VERSION 5.8 ;
BUSBITCHARS "[]" ;
DIVIDERCHAR "/" ;
UNITS
    DATABASE MICRONS 1000 ;
END UNITS

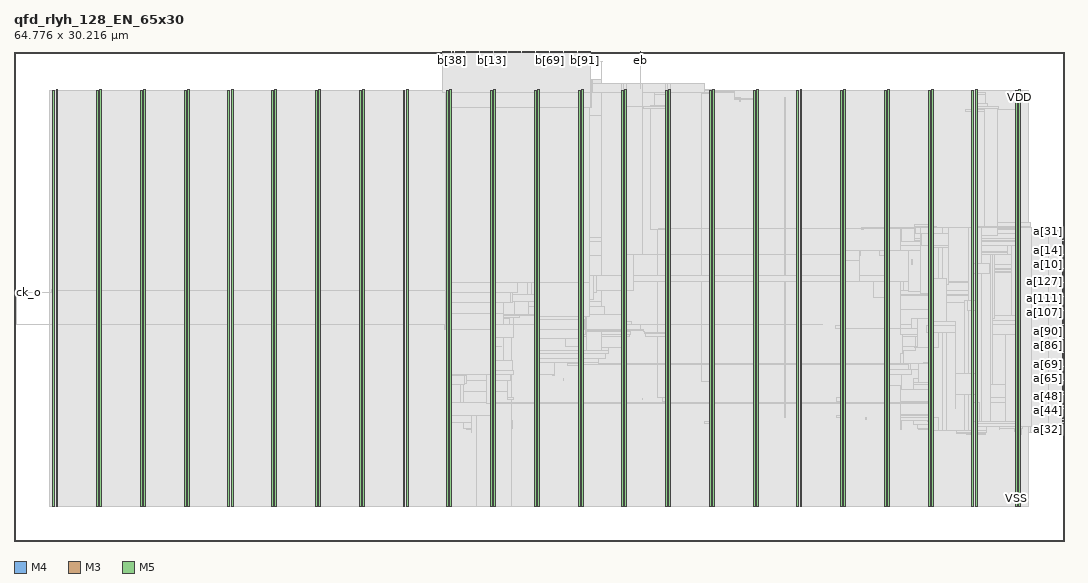
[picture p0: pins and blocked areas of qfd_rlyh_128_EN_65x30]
MACRO qfd_rlyh_128_EN_65x30
  FOREIGN qfd_rlyh_128_EN_65x30 0 0 ;
  CLASS BLOCK ;
  SIZE 64.776 BY 30.216 ;
  PIN a[0]
    DIRECTION INPUT ;
    USE SIGNAL ;
    PORT
      LAYER M4 ;
        RECT  64.692 16.08 64.776 16.104 ;
    END
  END a[0]
  PIN a[100]
    DIRECTION INPUT ;
    USE SIGNAL ;
    PORT
      LAYER M4 ;
        RECT  64.692 13.392 64.776 13.416 ;
    END
  END a[100]
  PIN a[101]
    DIRECTION INPUT ;
    USE SIGNAL ;
    PORT
      LAYER M4 ;
        RECT  64.692 13.488 64.776 13.512 ;
    END
  END a[101]
  PIN a[102]
    DIRECTION INPUT ;
    USE SIGNAL ;
    PORT
      LAYER M4 ;
        RECT  64.692 13.584 64.776 13.608 ;
    END
  END a[102]
  PIN a[103]
    DIRECTION INPUT ;
    USE SIGNAL ;
    PORT
      LAYER M4 ;
        RECT  64.692 13.68 64.776 13.704 ;
    END
  END a[103]
  PIN a[104]
    DIRECTION INPUT ;
    USE SIGNAL ;
    PORT
      LAYER M4 ;
        RECT  64.692 13.776 64.776 13.8 ;
    END
  END a[104]
  PIN a[105]
    DIRECTION INPUT ;
    USE SIGNAL ;
    PORT
      LAYER M4 ;
        RECT  64.692 13.872 64.776 13.896 ;
    END
  END a[105]
  PIN a[106]
    DIRECTION INPUT ;
    USE SIGNAL ;
    PORT
      LAYER M4 ;
        RECT  64.692 13.968 64.776 13.992 ;
    END
  END a[106]
  PIN a[107]
    DIRECTION INPUT ;
    USE SIGNAL ;
    PORT
      LAYER M4 ;
        RECT  64.692 14.064 64.776 14.088 ;
    END
  END a[107]
  PIN a[108]
    DIRECTION INPUT ;
    USE SIGNAL ;
    PORT
      LAYER M4 ;
        RECT  64.692 14.16 64.776 14.184 ;
    END
  END a[108]
  PIN a[109]
    DIRECTION INPUT ;
    USE SIGNAL ;
    PORT
      LAYER M4 ;
        RECT  64.692 14.256 64.776 14.28 ;
    END
  END a[109]
  PIN a[10]
    DIRECTION INPUT ;
    USE SIGNAL ;
    PORT
      LAYER M4 ;
        RECT  64.692 17.04 64.776 17.064 ;
    END
  END a[10]
  PIN a[110]
    DIRECTION INPUT ;
    USE SIGNAL ;
    PORT
      LAYER M4 ;
        RECT  64.692 14.352 64.776 14.376 ;
    END
  END a[110]
  PIN a[111]
    DIRECTION INPUT ;
    USE SIGNAL ;
    PORT
      LAYER M4 ;
        RECT  64.692 14.448 64.776 14.472 ;
    END
  END a[111]
  PIN a[112]
    DIRECTION INPUT ;
    USE SIGNAL ;
    PORT
      LAYER M4 ;
        RECT  64.692 14.544 64.776 14.568 ;
    END
  END a[112]
  PIN a[113]
    DIRECTION INPUT ;
    USE SIGNAL ;
    PORT
      LAYER M4 ;
        RECT  64.692 14.64 64.776 14.664 ;
    END
  END a[113]
  PIN a[114]
    DIRECTION INPUT ;
    USE SIGNAL ;
    PORT
      LAYER M4 ;
        RECT  64.692 14.736 64.776 14.76 ;
    END
  END a[114]
  PIN a[115]
    DIRECTION INPUT ;
    USE SIGNAL ;
    PORT
      LAYER M4 ;
        RECT  64.692 14.832 64.776 14.856 ;
    END
  END a[115]
  PIN a[116]
    DIRECTION INPUT ;
    USE SIGNAL ;
    PORT
      LAYER M4 ;
        RECT  64.692 14.928 64.776 14.952 ;
    END
  END a[116]
  PIN a[117]
    DIRECTION INPUT ;
    USE SIGNAL ;
    PORT
      LAYER M4 ;
        RECT  64.692 15.024 64.776 15.048 ;
    END
  END a[117]
  PIN a[118]
    DIRECTION INPUT ;
    USE SIGNAL ;
    PORT
      LAYER M4 ;
        RECT  64.692 15.12 64.776 15.144 ;
    END
  END a[118]
  PIN a[119]
    DIRECTION INPUT ;
    USE SIGNAL ;
    PORT
      LAYER M4 ;
        RECT  64.692 15.216 64.776 15.24 ;
    END
  END a[119]
  PIN a[11]
    DIRECTION INPUT ;
    USE SIGNAL ;
    PORT
      LAYER M4 ;
        RECT  64.692 17.136 64.776 17.16 ;
    END
  END a[11]
  PIN a[120]
    DIRECTION INPUT ;
    USE SIGNAL ;
    PORT
      LAYER M4 ;
        RECT  64.692 15.312 64.776 15.336 ;
    END
  END a[120]
  PIN a[121]
    DIRECTION INPUT ;
    USE SIGNAL ;
    PORT
      LAYER M4 ;
        RECT  64.692 15.408 64.776 15.432 ;
    END
  END a[121]
  PIN a[122]
    DIRECTION INPUT ;
    USE SIGNAL ;
    PORT
      LAYER M4 ;
        RECT  64.692 15.504 64.776 15.528 ;
    END
  END a[122]
  PIN a[123]
    DIRECTION INPUT ;
    USE SIGNAL ;
    PORT
      LAYER M4 ;
        RECT  64.692 15.6 64.776 15.624 ;
    END
  END a[123]
  PIN a[124]
    DIRECTION INPUT ;
    USE SIGNAL ;
    PORT
      LAYER M4 ;
        RECT  64.692 15.696 64.776 15.72 ;
    END
  END a[124]
  PIN a[125]
    DIRECTION INPUT ;
    USE SIGNAL ;
    PORT
      LAYER M4 ;
        RECT  64.692 15.792 64.776 15.816 ;
    END
  END a[125]
  PIN a[126]
    DIRECTION INPUT ;
    USE SIGNAL ;
    PORT
      LAYER M4 ;
        RECT  64.692 15.888 64.776 15.912 ;
    END
  END a[126]
  PIN a[127]
    DIRECTION INPUT ;
    USE SIGNAL ;
    PORT
      LAYER M4 ;
        RECT  64.692 15.984 64.776 16.008 ;
    END
  END a[127]
  PIN a[12]
    DIRECTION INPUT ;
    USE SIGNAL ;
    PORT
      LAYER M4 ;
        RECT  64.692 17.232 64.776 17.256 ;
    END
  END a[12]
  PIN a[13]
    DIRECTION INPUT ;
    USE SIGNAL ;
    PORT
      LAYER M4 ;
        RECT  64.692 17.328 64.776 17.352 ;
    END
  END a[13]
  PIN a[14]
    DIRECTION INPUT ;
    USE SIGNAL ;
    PORT
      LAYER M4 ;
        RECT  64.692 17.424 64.776 17.448 ;
    END
  END a[14]
  PIN a[15]
    DIRECTION INPUT ;
    USE SIGNAL ;
    PORT
      LAYER M4 ;
        RECT  64.692 17.52 64.776 17.544 ;
    END
  END a[15]
  PIN a[16]
    DIRECTION INPUT ;
    USE SIGNAL ;
    PORT
      LAYER M4 ;
        RECT  64.692 17.616 64.776 17.64 ;
    END
  END a[16]
  PIN a[17]
    DIRECTION INPUT ;
    USE SIGNAL ;
    PORT
      LAYER M4 ;
        RECT  64.692 17.712 64.776 17.736 ;
    END
  END a[17]
  PIN a[18]
    DIRECTION INPUT ;
    USE SIGNAL ;
    PORT
      LAYER M4 ;
        RECT  64.692 17.808 64.776 17.832 ;
    END
  END a[18]
  PIN a[19]
    DIRECTION INPUT ;
    USE SIGNAL ;
    PORT
      LAYER M4 ;
        RECT  64.692 17.904 64.776 17.928 ;
    END
  END a[19]
  PIN a[1]
    DIRECTION INPUT ;
    USE SIGNAL ;
    PORT
      LAYER M4 ;
        RECT  64.692 16.176 64.776 16.2 ;
    END
  END a[1]
  PIN a[20]
    DIRECTION INPUT ;
    USE SIGNAL ;
    PORT
      LAYER M4 ;
        RECT  64.692 18 64.776 18.024 ;
    END
  END a[20]
  PIN a[21]
    DIRECTION INPUT ;
    USE SIGNAL ;
    PORT
      LAYER M4 ;
        RECT  64.692 18.096 64.776 18.12 ;
    END
  END a[21]
  PIN a[22]
    DIRECTION INPUT ;
    USE SIGNAL ;
    PORT
      LAYER M4 ;
        RECT  64.692 18.192 64.776 18.216 ;
    END
  END a[22]
  PIN a[23]
    DIRECTION INPUT ;
    USE SIGNAL ;
    PORT
      LAYER M4 ;
        RECT  64.692 18.288 64.776 18.312 ;
    END
  END a[23]
  PIN a[24]
    DIRECTION INPUT ;
    USE SIGNAL ;
    PORT
      LAYER M4 ;
        RECT  64.692 18.384 64.776 18.408 ;
    END
  END a[24]
  PIN a[25]
    DIRECTION INPUT ;
    USE SIGNAL ;
    PORT
      LAYER M4 ;
        RECT  64.692 18.48 64.776 18.504 ;
    END
  END a[25]
  PIN a[26]
    DIRECTION INPUT ;
    USE SIGNAL ;
    PORT
      LAYER M4 ;
        RECT  64.692 18.576 64.776 18.6 ;
    END
  END a[26]
  PIN a[27]
    DIRECTION INPUT ;
    USE SIGNAL ;
    PORT
      LAYER M4 ;
        RECT  64.692 18.672 64.776 18.696 ;
    END
  END a[27]
  PIN a[28]
    DIRECTION INPUT ;
    USE SIGNAL ;
    PORT
      LAYER M4 ;
        RECT  64.692 18.768 64.776 18.792 ;
    END
  END a[28]
  PIN a[29]
    DIRECTION INPUT ;
    USE SIGNAL ;
    PORT
      LAYER M4 ;
        RECT  64.692 18.864 64.776 18.888 ;
    END
  END a[29]
  PIN a[2]
    DIRECTION INPUT ;
    USE SIGNAL ;
    PORT
      LAYER M4 ;
        RECT  64.692 16.272 64.776 16.296 ;
    END
  END a[2]
  PIN a[30]
    DIRECTION INPUT ;
    USE SIGNAL ;
    PORT
      LAYER M4 ;
        RECT  64.692 18.96 64.776 18.984 ;
    END
  END a[30]
  PIN a[31]
    DIRECTION INPUT ;
    USE SIGNAL ;
    PORT
      LAYER M4 ;
        RECT  64.692 19.056 64.776 19.08 ;
    END
  END a[31]
  PIN a[32]
    DIRECTION INPUT ;
    USE SIGNAL ;
    PORT
      LAYER M4 ;
        RECT  64.692 6.864 64.776 6.888 ;
    END
  END a[32]
  PIN a[33]
    DIRECTION INPUT ;
    USE SIGNAL ;
    PORT
      LAYER M4 ;
        RECT  64.692 6.96 64.776 6.984 ;
    END
  END a[33]
  PIN a[34]
    DIRECTION INPUT ;
    USE SIGNAL ;
    PORT
      LAYER M4 ;
        RECT  64.692 7.056 64.776 7.08 ;
    END
  END a[34]
  PIN a[35]
    DIRECTION INPUT ;
    USE SIGNAL ;
    PORT
      LAYER M4 ;
        RECT  64.692 7.152 64.776 7.176 ;
    END
  END a[35]
  PIN a[36]
    DIRECTION INPUT ;
    USE SIGNAL ;
    PORT
      LAYER M4 ;
        RECT  64.692 7.248 64.776 7.272 ;
    END
  END a[36]
  PIN a[37]
    DIRECTION INPUT ;
    USE SIGNAL ;
    PORT
      LAYER M4 ;
        RECT  64.692 7.344 64.776 7.368 ;
    END
  END a[37]
  PIN a[38]
    DIRECTION INPUT ;
    USE SIGNAL ;
    PORT
      LAYER M4 ;
        RECT  64.692 7.44 64.776 7.464 ;
    END
  END a[38]
  PIN a[39]
    DIRECTION INPUT ;
    USE SIGNAL ;
    PORT
      LAYER M4 ;
        RECT  64.692 7.536 64.776 7.56 ;
    END
  END a[39]
  PIN a[3]
    DIRECTION INPUT ;
    USE SIGNAL ;
    PORT
      LAYER M4 ;
        RECT  64.692 16.368 64.776 16.392 ;
    END
  END a[3]
  PIN a[40]
    DIRECTION INPUT ;
    USE SIGNAL ;
    PORT
      LAYER M4 ;
        RECT  64.692 7.632 64.776 7.656 ;
    END
  END a[40]
  PIN a[41]
    DIRECTION INPUT ;
    USE SIGNAL ;
    PORT
      LAYER M4 ;
        RECT  64.692 7.728 64.776 7.752 ;
    END
  END a[41]
  PIN a[42]
    DIRECTION INPUT ;
    USE SIGNAL ;
    PORT
      LAYER M4 ;
        RECT  64.692 7.824 64.776 7.848 ;
    END
  END a[42]
  PIN a[43]
    DIRECTION INPUT ;
    USE SIGNAL ;
    PORT
      LAYER M4 ;
        RECT  64.692 7.92 64.776 7.944 ;
    END
  END a[43]
  PIN a[44]
    DIRECTION INPUT ;
    USE SIGNAL ;
    PORT
      LAYER M4 ;
        RECT  64.692 8.016 64.776 8.04 ;
    END
  END a[44]
  PIN a[45]
    DIRECTION INPUT ;
    USE SIGNAL ;
    PORT
      LAYER M4 ;
        RECT  64.692 8.112 64.776 8.136 ;
    END
  END a[45]
  PIN a[46]
    DIRECTION INPUT ;
    USE SIGNAL ;
    PORT
      LAYER M4 ;
        RECT  64.692 8.208 64.776 8.232 ;
    END
  END a[46]
  PIN a[47]
    DIRECTION INPUT ;
    USE SIGNAL ;
    PORT
      LAYER M4 ;
        RECT  64.692 8.304 64.776 8.328 ;
    END
  END a[47]
  PIN a[48]
    DIRECTION INPUT ;
    USE SIGNAL ;
    PORT
      LAYER M4 ;
        RECT  64.692 8.4 64.776 8.424 ;
    END
  END a[48]
  PIN a[49]
    DIRECTION INPUT ;
    USE SIGNAL ;
    PORT
      LAYER M4 ;
        RECT  64.692 8.496 64.776 8.52 ;
    END
  END a[49]
  PIN a[4]
    DIRECTION INPUT ;
    USE SIGNAL ;
    PORT
      LAYER M4 ;
        RECT  64.692 16.464 64.776 16.488 ;
    END
  END a[4]
  PIN a[50]
    DIRECTION INPUT ;
    USE SIGNAL ;
    PORT
      LAYER M4 ;
        RECT  64.692 8.592 64.776 8.616 ;
    END
  END a[50]
  PIN a[51]
    DIRECTION INPUT ;
    USE SIGNAL ;
    PORT
      LAYER M4 ;
        RECT  64.692 8.688 64.776 8.712 ;
    END
  END a[51]
  PIN a[52]
    DIRECTION INPUT ;
    USE SIGNAL ;
    PORT
      LAYER M4 ;
        RECT  64.692 8.784 64.776 8.808 ;
    END
  END a[52]
  PIN a[53]
    DIRECTION INPUT ;
    USE SIGNAL ;
    PORT
      LAYER M4 ;
        RECT  64.692 8.88 64.776 8.904 ;
    END
  END a[53]
  PIN a[54]
    DIRECTION INPUT ;
    USE SIGNAL ;
    PORT
      LAYER M4 ;
        RECT  64.692 8.976 64.776 9 ;
    END
  END a[54]
  PIN a[55]
    DIRECTION INPUT ;
    USE SIGNAL ;
    PORT
      LAYER M4 ;
        RECT  64.692 9.072 64.776 9.096 ;
    END
  END a[55]
  PIN a[56]
    DIRECTION INPUT ;
    USE SIGNAL ;
    PORT
      LAYER M4 ;
        RECT  64.692 9.168 64.776 9.192 ;
    END
  END a[56]
  PIN a[57]
    DIRECTION INPUT ;
    USE SIGNAL ;
    PORT
      LAYER M4 ;
        RECT  64.692 9.264 64.776 9.288 ;
    END
  END a[57]
  PIN a[58]
    DIRECTION INPUT ;
    USE SIGNAL ;
    PORT
      LAYER M4 ;
        RECT  64.692 9.36 64.776 9.384 ;
    END
  END a[58]
  PIN a[59]
    DIRECTION INPUT ;
    USE SIGNAL ;
    PORT
      LAYER M4 ;
        RECT  64.692 9.456 64.776 9.48 ;
    END
  END a[59]
  PIN a[5]
    DIRECTION INPUT ;
    USE SIGNAL ;
    PORT
      LAYER M4 ;
        RECT  64.692 16.56 64.776 16.584 ;
    END
  END a[5]
  PIN a[60]
    DIRECTION INPUT ;
    USE SIGNAL ;
    PORT
      LAYER M4 ;
        RECT  64.692 9.552 64.776 9.576 ;
    END
  END a[60]
  PIN a[61]
    DIRECTION INPUT ;
    USE SIGNAL ;
    PORT
      LAYER M4 ;
        RECT  64.692 9.648 64.776 9.672 ;
    END
  END a[61]
  PIN a[62]
    DIRECTION INPUT ;
    USE SIGNAL ;
    PORT
      LAYER M4 ;
        RECT  64.692 9.744 64.776 9.768 ;
    END
  END a[62]
  PIN a[63]
    DIRECTION INPUT ;
    USE SIGNAL ;
    PORT
      LAYER M4 ;
        RECT  64.692 9.84 64.776 9.864 ;
    END
  END a[63]
  PIN a[64]
    DIRECTION INPUT ;
    USE SIGNAL ;
    PORT
      LAYER M4 ;
        RECT  64.692 9.936 64.776 9.96 ;
    END
  END a[64]
  PIN a[65]
    DIRECTION INPUT ;
    USE SIGNAL ;
    PORT
      LAYER M4 ;
        RECT  64.692 10.032 64.776 10.056 ;
    END
  END a[65]
  PIN a[66]
    DIRECTION INPUT ;
    USE SIGNAL ;
    PORT
      LAYER M4 ;
        RECT  64.692 10.128 64.776 10.152 ;
    END
  END a[66]
  PIN a[67]
    DIRECTION INPUT ;
    USE SIGNAL ;
    PORT
      LAYER M4 ;
        RECT  64.692 10.224 64.776 10.248 ;
    END
  END a[67]
  PIN a[68]
    DIRECTION INPUT ;
    USE SIGNAL ;
    PORT
      LAYER M4 ;
        RECT  64.692 10.32 64.776 10.344 ;
    END
  END a[68]
  PIN a[69]
    DIRECTION INPUT ;
    USE SIGNAL ;
    PORT
      LAYER M4 ;
        RECT  64.692 10.416 64.776 10.44 ;
    END
  END a[69]
  PIN a[6]
    DIRECTION INPUT ;
    USE SIGNAL ;
    PORT
      LAYER M4 ;
        RECT  64.692 16.656 64.776 16.68 ;
    END
  END a[6]
  PIN a[70]
    DIRECTION INPUT ;
    USE SIGNAL ;
    PORT
      LAYER M4 ;
        RECT  64.692 10.512 64.776 10.536 ;
    END
  END a[70]
  PIN a[71]
    DIRECTION INPUT ;
    USE SIGNAL ;
    PORT
      LAYER M4 ;
        RECT  64.692 10.608 64.776 10.632 ;
    END
  END a[71]
  PIN a[72]
    DIRECTION INPUT ;
    USE SIGNAL ;
    PORT
      LAYER M4 ;
        RECT  64.692 10.704 64.776 10.728 ;
    END
  END a[72]
  PIN a[73]
    DIRECTION INPUT ;
    USE SIGNAL ;
    PORT
      LAYER M4 ;
        RECT  64.692 10.8 64.776 10.824 ;
    END
  END a[73]
  PIN a[74]
    DIRECTION INPUT ;
    USE SIGNAL ;
    PORT
      LAYER M4 ;
        RECT  64.692 10.896 64.776 10.92 ;
    END
  END a[74]
  PIN a[75]
    DIRECTION INPUT ;
    USE SIGNAL ;
    PORT
      LAYER M4 ;
        RECT  64.692 10.992 64.776 11.016 ;
    END
  END a[75]
  PIN a[76]
    DIRECTION INPUT ;
    USE SIGNAL ;
    PORT
      LAYER M4 ;
        RECT  64.692 11.088 64.776 11.112 ;
    END
  END a[76]
  PIN a[77]
    DIRECTION INPUT ;
    USE SIGNAL ;
    PORT
      LAYER M4 ;
        RECT  64.692 11.184 64.776 11.208 ;
    END
  END a[77]
  PIN a[78]
    DIRECTION INPUT ;
    USE SIGNAL ;
    PORT
      LAYER M4 ;
        RECT  64.692 11.28 64.776 11.304 ;
    END
  END a[78]
  PIN a[79]
    DIRECTION INPUT ;
    USE SIGNAL ;
    PORT
      LAYER M4 ;
        RECT  64.692 11.376 64.776 11.4 ;
    END
  END a[79]
  PIN a[7]
    DIRECTION INPUT ;
    USE SIGNAL ;
    PORT
      LAYER M4 ;
        RECT  64.692 16.752 64.776 16.776 ;
    END
  END a[7]
  PIN a[80]
    DIRECTION INPUT ;
    USE SIGNAL ;
    PORT
      LAYER M4 ;
        RECT  64.692 11.472 64.776 11.496 ;
    END
  END a[80]
  PIN a[81]
    DIRECTION INPUT ;
    USE SIGNAL ;
    PORT
      LAYER M4 ;
        RECT  64.692 11.568 64.776 11.592 ;
    END
  END a[81]
  PIN a[82]
    DIRECTION INPUT ;
    USE SIGNAL ;
    PORT
      LAYER M4 ;
        RECT  64.692 11.664 64.776 11.688 ;
    END
  END a[82]
  PIN a[83]
    DIRECTION INPUT ;
    USE SIGNAL ;
    PORT
      LAYER M4 ;
        RECT  64.692 11.76 64.776 11.784 ;
    END
  END a[83]
  PIN a[84]
    DIRECTION INPUT ;
    USE SIGNAL ;
    PORT
      LAYER M4 ;
        RECT  64.692 11.856 64.776 11.88 ;
    END
  END a[84]
  PIN a[85]
    DIRECTION INPUT ;
    USE SIGNAL ;
    PORT
      LAYER M4 ;
        RECT  64.692 11.952 64.776 11.976 ;
    END
  END a[85]
  PIN a[86]
    DIRECTION INPUT ;
    USE SIGNAL ;
    PORT
      LAYER M4 ;
        RECT  64.692 12.048 64.776 12.072 ;
    END
  END a[86]
  PIN a[87]
    DIRECTION INPUT ;
    USE SIGNAL ;
    PORT
      LAYER M4 ;
        RECT  64.692 12.144 64.776 12.168 ;
    END
  END a[87]
  PIN a[88]
    DIRECTION INPUT ;
    USE SIGNAL ;
    PORT
      LAYER M4 ;
        RECT  64.692 12.24 64.776 12.264 ;
    END
  END a[88]
  PIN a[89]
    DIRECTION INPUT ;
    USE SIGNAL ;
    PORT
      LAYER M4 ;
        RECT  64.692 12.336 64.776 12.36 ;
    END
  END a[89]
  PIN a[8]
    DIRECTION INPUT ;
    USE SIGNAL ;
    PORT
      LAYER M4 ;
        RECT  64.692 16.848 64.776 16.872 ;
    END
  END a[8]
  PIN a[90]
    DIRECTION INPUT ;
    USE SIGNAL ;
    PORT
      LAYER M4 ;
        RECT  64.692 12.432 64.776 12.456 ;
    END
  END a[90]
  PIN a[91]
    DIRECTION INPUT ;
    USE SIGNAL ;
    PORT
      LAYER M4 ;
        RECT  64.692 12.528 64.776 12.552 ;
    END
  END a[91]
  PIN a[92]
    DIRECTION INPUT ;
    USE SIGNAL ;
    PORT
      LAYER M4 ;
        RECT  64.692 12.624 64.776 12.648 ;
    END
  END a[92]
  PIN a[93]
    DIRECTION INPUT ;
    USE SIGNAL ;
    PORT
      LAYER M4 ;
        RECT  64.692 12.72 64.776 12.744 ;
    END
  END a[93]
  PIN a[94]
    DIRECTION INPUT ;
    USE SIGNAL ;
    PORT
      LAYER M4 ;
        RECT  64.692 12.816 64.776 12.84 ;
    END
  END a[94]
  PIN a[95]
    DIRECTION INPUT ;
    USE SIGNAL ;
    PORT
      LAYER M4 ;
        RECT  64.692 12.912 64.776 12.936 ;
    END
  END a[95]
  PIN a[96]
    DIRECTION INPUT ;
    USE SIGNAL ;
    PORT
      LAYER M4 ;
        RECT  64.692 13.008 64.776 13.032 ;
    END
  END a[96]
  PIN a[97]
    DIRECTION INPUT ;
    USE SIGNAL ;
    PORT
      LAYER M4 ;
        RECT  64.692 13.104 64.776 13.128 ;
    END
  END a[97]
  PIN a[98]
    DIRECTION INPUT ;
    USE SIGNAL ;
    PORT
      LAYER M4 ;
        RECT  64.692 13.2 64.776 13.224 ;
    END
  END a[98]
  PIN a[99]
    DIRECTION INPUT ;
    USE SIGNAL ;
    PORT
      LAYER M4 ;
        RECT  64.692 13.296 64.776 13.32 ;
    END
  END a[99]
  PIN a[9]
    DIRECTION INPUT ;
    USE SIGNAL ;
    PORT
      LAYER M4 ;
        RECT  64.692 16.944 64.776 16.968 ;
    END
  END a[9]
  PIN b[0]
    DIRECTION OUTPUT ;
    USE SIGNAL ;
    PORT
      LAYER M3 ;
        RECT  28.548 30.179 28.566 30.216 ;
    END
  END b[0]
  PIN b[100]
    DIRECTION OUTPUT ;
    USE SIGNAL ;
    PORT
      LAYER M5 ;
        RECT  29.904 30.132 29.928 30.216 ;
    END
  END b[100]
  PIN b[101]
    DIRECTION OUTPUT ;
    USE SIGNAL ;
    PORT
      LAYER M5 ;
        RECT  30 30.132 30.024 30.216 ;
    END
  END b[101]
  PIN b[102]
    DIRECTION OUTPUT ;
    USE SIGNAL ;
    PORT
      LAYER M5 ;
        RECT  30.096 30.132 30.12 30.216 ;
    END
  END b[102]
  PIN b[103]
    DIRECTION OUTPUT ;
    USE SIGNAL ;
    PORT
      LAYER M5 ;
        RECT  30.192 30.132 30.216 30.216 ;
    END
  END b[103]
  PIN b[104]
    DIRECTION OUTPUT ;
    USE SIGNAL ;
    PORT
      LAYER M5 ;
        RECT  30.288 30.132 30.312 30.216 ;
    END
  END b[104]
  PIN b[105]
    DIRECTION OUTPUT ;
    USE SIGNAL ;
    PORT
      LAYER M5 ;
        RECT  30.384 30.132 30.408 30.216 ;
    END
  END b[105]
  PIN b[106]
    DIRECTION OUTPUT ;
    USE SIGNAL ;
    PORT
      LAYER M5 ;
        RECT  30.48 30.132 30.504 30.216 ;
    END
  END b[106]
  PIN b[107]
    DIRECTION OUTPUT ;
    USE SIGNAL ;
    PORT
      LAYER M5 ;
        RECT  30.576 30.132 30.6 30.216 ;
    END
  END b[107]
  PIN b[108]
    DIRECTION OUTPUT ;
    USE SIGNAL ;
    PORT
      LAYER M5 ;
        RECT  30.672 30.132 30.696 30.216 ;
    END
  END b[108]
  PIN b[109]
    DIRECTION OUTPUT ;
    USE SIGNAL ;
    PORT
      LAYER M5 ;
        RECT  30.768 30.132 30.792 30.216 ;
    END
  END b[109]
  PIN b[10]
    DIRECTION OUTPUT ;
    USE SIGNAL ;
    PORT
      LAYER M3 ;
        RECT  29.268 30.179 29.286 30.216 ;
    END
  END b[10]
  PIN b[110]
    DIRECTION OUTPUT ;
    USE SIGNAL ;
    PORT
      LAYER M5 ;
        RECT  30.864 30.132 30.888 30.216 ;
    END
  END b[110]
  PIN b[111]
    DIRECTION OUTPUT ;
    USE SIGNAL ;
    PORT
      LAYER M5 ;
        RECT  30.96 30.132 30.984 30.216 ;
    END
  END b[111]
  PIN b[112]
    DIRECTION OUTPUT ;
    USE SIGNAL ;
    PORT
      LAYER M5 ;
        RECT  31.056 30.132 31.08 30.216 ;
    END
  END b[112]
  PIN b[113]
    DIRECTION OUTPUT ;
    USE SIGNAL ;
    PORT
      LAYER M5 ;
        RECT  31.152 30.132 31.176 30.216 ;
    END
  END b[113]
  PIN b[114]
    DIRECTION OUTPUT ;
    USE SIGNAL ;
    PORT
      LAYER M5 ;
        RECT  31.248 30.132 31.272 30.216 ;
    END
  END b[114]
  PIN b[115]
    DIRECTION OUTPUT ;
    USE SIGNAL ;
    PORT
      LAYER M5 ;
        RECT  31.344 30.132 31.368 30.216 ;
    END
  END b[115]
  PIN b[116]
    DIRECTION OUTPUT ;
    USE SIGNAL ;
    PORT
      LAYER M5 ;
        RECT  31.44 30.132 31.464 30.216 ;
    END
  END b[116]
  PIN b[117]
    DIRECTION OUTPUT ;
    USE SIGNAL ;
    PORT
      LAYER M5 ;
        RECT  31.536 30.132 31.56 30.216 ;
    END
  END b[117]
  PIN b[118]
    DIRECTION OUTPUT ;
    USE SIGNAL ;
    PORT
      LAYER M5 ;
        RECT  31.632 30.132 31.656 30.216 ;
    END
  END b[118]
  PIN b[119]
    DIRECTION OUTPUT ;
    USE SIGNAL ;
    PORT
      LAYER M5 ;
        RECT  31.728 30.132 31.752 30.216 ;
    END
  END b[119]
  PIN b[11]
    DIRECTION OUTPUT ;
    USE SIGNAL ;
    PORT
      LAYER M3 ;
        RECT  29.34 30.179 29.358 30.216 ;
    END
  END b[11]
  PIN b[120]
    DIRECTION OUTPUT ;
    USE SIGNAL ;
    PORT
      LAYER M5 ;
        RECT  31.824 30.132 31.848 30.216 ;
    END
  END b[120]
  PIN b[121]
    DIRECTION OUTPUT ;
    USE SIGNAL ;
    PORT
      LAYER M5 ;
        RECT  31.92 30.132 31.944 30.216 ;
    END
  END b[121]
  PIN b[122]
    DIRECTION OUTPUT ;
    USE SIGNAL ;
    PORT
      LAYER M5 ;
        RECT  32.016 30.132 32.04 30.216 ;
    END
  END b[122]
  PIN b[123]
    DIRECTION OUTPUT ;
    USE SIGNAL ;
    PORT
      LAYER M5 ;
        RECT  32.112 30.132 32.136 30.216 ;
    END
  END b[123]
  PIN b[124]
    DIRECTION OUTPUT ;
    USE SIGNAL ;
    PORT
      LAYER M5 ;
        RECT  32.208 30.132 32.232 30.216 ;
    END
  END b[124]
  PIN b[125]
    DIRECTION OUTPUT ;
    USE SIGNAL ;
    PORT
      LAYER M5 ;
        RECT  32.304 30.132 32.328 30.216 ;
    END
  END b[125]
  PIN b[126]
    DIRECTION OUTPUT ;
    USE SIGNAL ;
    PORT
      LAYER M5 ;
        RECT  32.4 30.132 32.424 30.216 ;
    END
  END b[126]
  PIN b[127]
    DIRECTION OUTPUT ;
    USE SIGNAL ;
    PORT
      LAYER M5 ;
        RECT  32.496 30.132 32.52 30.216 ;
    END
  END b[127]
  PIN b[12]
    DIRECTION OUTPUT ;
    USE SIGNAL ;
    PORT
      LAYER M3 ;
        RECT  29.412 30.179 29.43 30.216 ;
    END
  END b[12]
  PIN b[13]
    DIRECTION OUTPUT ;
    USE SIGNAL ;
    PORT
      LAYER M3 ;
        RECT  29.484 30.179 29.502 30.216 ;
    END
  END b[13]
  PIN b[14]
    DIRECTION OUTPUT ;
    USE SIGNAL ;
    PORT
      LAYER M3 ;
        RECT  29.556 30.179 29.574 30.216 ;
    END
  END b[14]
  PIN b[15]
    DIRECTION OUTPUT ;
    USE SIGNAL ;
    PORT
      LAYER M3 ;
        RECT  29.628 30.179 29.646 30.216 ;
    END
  END b[15]
  PIN b[16]
    DIRECTION OUTPUT ;
    USE SIGNAL ;
    PORT
      LAYER M3 ;
        RECT  29.7 30.179 29.718 30.216 ;
    END
  END b[16]
  PIN b[17]
    DIRECTION OUTPUT ;
    USE SIGNAL ;
    PORT
      LAYER M3 ;
        RECT  29.772 30.179 29.79 30.216 ;
    END
  END b[17]
  PIN b[18]
    DIRECTION OUTPUT ;
    USE SIGNAL ;
    PORT
      LAYER M3 ;
        RECT  29.844 30.179 29.862 30.216 ;
    END
  END b[18]
  PIN b[19]
    DIRECTION OUTPUT ;
    USE SIGNAL ;
    PORT
      LAYER M3 ;
        RECT  29.916 30.179 29.934 30.216 ;
    END
  END b[19]
  PIN b[1]
    DIRECTION OUTPUT ;
    USE SIGNAL ;
    PORT
      LAYER M3 ;
        RECT  28.62 30.179 28.638 30.216 ;
    END
  END b[1]
  PIN b[20]
    DIRECTION OUTPUT ;
    USE SIGNAL ;
    PORT
      LAYER M3 ;
        RECT  29.988 30.179 30.006 30.216 ;
    END
  END b[20]
  PIN b[21]
    DIRECTION OUTPUT ;
    USE SIGNAL ;
    PORT
      LAYER M3 ;
        RECT  30.06 30.179 30.078 30.216 ;
    END
  END b[21]
  PIN b[22]
    DIRECTION OUTPUT ;
    USE SIGNAL ;
    PORT
      LAYER M3 ;
        RECT  30.132 30.179 30.15 30.216 ;
    END
  END b[22]
  PIN b[23]
    DIRECTION OUTPUT ;
    USE SIGNAL ;
    PORT
      LAYER M3 ;
        RECT  30.204 30.179 30.222 30.216 ;
    END
  END b[23]
  PIN b[24]
    DIRECTION OUTPUT ;
    USE SIGNAL ;
    PORT
      LAYER M3 ;
        RECT  30.276 30.179 30.294 30.216 ;
    END
  END b[24]
  PIN b[25]
    DIRECTION OUTPUT ;
    USE SIGNAL ;
    PORT
      LAYER M3 ;
        RECT  30.348 30.179 30.366 30.216 ;
    END
  END b[25]
  PIN b[26]
    DIRECTION OUTPUT ;
    USE SIGNAL ;
    PORT
      LAYER M3 ;
        RECT  30.42 30.179 30.438 30.216 ;
    END
  END b[26]
  PIN b[27]
    DIRECTION OUTPUT ;
    USE SIGNAL ;
    PORT
      LAYER M3 ;
        RECT  30.492 30.179 30.51 30.216 ;
    END
  END b[27]
  PIN b[28]
    DIRECTION OUTPUT ;
    USE SIGNAL ;
    PORT
      LAYER M3 ;
        RECT  30.564 30.179 30.582 30.216 ;
    END
  END b[28]
  PIN b[29]
    DIRECTION OUTPUT ;
    USE SIGNAL ;
    PORT
      LAYER M3 ;
        RECT  30.636 30.179 30.654 30.216 ;
    END
  END b[29]
  PIN b[2]
    DIRECTION OUTPUT ;
    USE SIGNAL ;
    PORT
      LAYER M3 ;
        RECT  28.692 30.179 28.71 30.216 ;
    END
  END b[2]
  PIN b[30]
    DIRECTION OUTPUT ;
    USE SIGNAL ;
    PORT
      LAYER M3 ;
        RECT  30.708 30.179 30.726 30.216 ;
    END
  END b[30]
  PIN b[31]
    DIRECTION OUTPUT ;
    USE SIGNAL ;
    PORT
      LAYER M3 ;
        RECT  30.78 30.179 30.798 30.216 ;
    END
  END b[31]
  PIN b[32]
    DIRECTION OUTPUT ;
    USE SIGNAL ;
    PORT
      LAYER M5 ;
        RECT  26.448 30.132 26.472 30.216 ;
    END
  END b[32]
  PIN b[33]
    DIRECTION OUTPUT ;
    USE SIGNAL ;
    PORT
      LAYER M5 ;
        RECT  26.544 30.132 26.568 30.216 ;
    END
  END b[33]
  PIN b[34]
    DIRECTION OUTPUT ;
    USE SIGNAL ;
    PORT
      LAYER M5 ;
        RECT  26.64 30.132 26.664 30.216 ;
    END
  END b[34]
  PIN b[35]
    DIRECTION OUTPUT ;
    USE SIGNAL ;
    PORT
      LAYER M5 ;
        RECT  26.736 30.132 26.76 30.216 ;
    END
  END b[35]
  PIN b[36]
    DIRECTION OUTPUT ;
    USE SIGNAL ;
    PORT
      LAYER M5 ;
        RECT  26.832 30.132 26.856 30.216 ;
    END
  END b[36]
  PIN b[37]
    DIRECTION OUTPUT ;
    USE SIGNAL ;
    PORT
      LAYER M5 ;
        RECT  26.928 30.132 26.952 30.216 ;
    END
  END b[37]
  PIN b[38]
    DIRECTION OUTPUT ;
    USE SIGNAL ;
    PORT
      LAYER M5 ;
        RECT  27.024 30.132 27.048 30.216 ;
    END
  END b[38]
  PIN b[39]
    DIRECTION OUTPUT ;
    USE SIGNAL ;
    PORT
      LAYER M5 ;
        RECT  27.12 30.132 27.144 30.216 ;
    END
  END b[39]
  PIN b[3]
    DIRECTION OUTPUT ;
    USE SIGNAL ;
    PORT
      LAYER M3 ;
        RECT  28.764 30.179 28.782 30.216 ;
    END
  END b[3]
  PIN b[40]
    DIRECTION OUTPUT ;
    USE SIGNAL ;
    PORT
      LAYER M5 ;
        RECT  27.216 30.132 27.24 30.216 ;
    END
  END b[40]
  PIN b[41]
    DIRECTION OUTPUT ;
    USE SIGNAL ;
    PORT
      LAYER M5 ;
        RECT  27.312 30.132 27.336 30.216 ;
    END
  END b[41]
  PIN b[42]
    DIRECTION OUTPUT ;
    USE SIGNAL ;
    PORT
      LAYER M5 ;
        RECT  27.408 30.132 27.432 30.216 ;
    END
  END b[42]
  PIN b[43]
    DIRECTION OUTPUT ;
    USE SIGNAL ;
    PORT
      LAYER M5 ;
        RECT  27.504 30.132 27.528 30.216 ;
    END
  END b[43]
  PIN b[44]
    DIRECTION OUTPUT ;
    USE SIGNAL ;
    PORT
      LAYER M5 ;
        RECT  27.6 30.132 27.624 30.216 ;
    END
  END b[44]
  PIN b[45]
    DIRECTION OUTPUT ;
    USE SIGNAL ;
    PORT
      LAYER M5 ;
        RECT  27.696 30.132 27.72 30.216 ;
    END
  END b[45]
  PIN b[46]
    DIRECTION OUTPUT ;
    USE SIGNAL ;
    PORT
      LAYER M5 ;
        RECT  27.792 30.132 27.816 30.216 ;
    END
  END b[46]
  PIN b[47]
    DIRECTION OUTPUT ;
    USE SIGNAL ;
    PORT
      LAYER M5 ;
        RECT  27.888 30.132 27.912 30.216 ;
    END
  END b[47]
  PIN b[48]
    DIRECTION OUTPUT ;
    USE SIGNAL ;
    PORT
      LAYER M5 ;
        RECT  27.984 30.132 28.008 30.216 ;
    END
  END b[48]
  PIN b[49]
    DIRECTION OUTPUT ;
    USE SIGNAL ;
    PORT
      LAYER M5 ;
        RECT  28.08 30.132 28.104 30.216 ;
    END
  END b[49]
  PIN b[4]
    DIRECTION OUTPUT ;
    USE SIGNAL ;
    PORT
      LAYER M3 ;
        RECT  28.836 30.179 28.854 30.216 ;
    END
  END b[4]
  PIN b[50]
    DIRECTION OUTPUT ;
    USE SIGNAL ;
    PORT
      LAYER M5 ;
        RECT  28.176 30.132 28.2 30.216 ;
    END
  END b[50]
  PIN b[51]
    DIRECTION OUTPUT ;
    USE SIGNAL ;
    PORT
      LAYER M5 ;
        RECT  28.272 30.132 28.296 30.216 ;
    END
  END b[51]
  PIN b[52]
    DIRECTION OUTPUT ;
    USE SIGNAL ;
    PORT
      LAYER M5 ;
        RECT  28.368 30.132 28.392 30.216 ;
    END
  END b[52]
  PIN b[53]
    DIRECTION OUTPUT ;
    USE SIGNAL ;
    PORT
      LAYER M5 ;
        RECT  28.464 30.132 28.488 30.216 ;
    END
  END b[53]
  PIN b[54]
    DIRECTION OUTPUT ;
    USE SIGNAL ;
    PORT
      LAYER M5 ;
        RECT  28.56 30.132 28.584 30.216 ;
    END
  END b[54]
  PIN b[55]
    DIRECTION OUTPUT ;
    USE SIGNAL ;
    PORT
      LAYER M5 ;
        RECT  28.656 30.132 28.68 30.216 ;
    END
  END b[55]
  PIN b[56]
    DIRECTION OUTPUT ;
    USE SIGNAL ;
    PORT
      LAYER M5 ;
        RECT  28.752 30.132 28.776 30.216 ;
    END
  END b[56]
  PIN b[57]
    DIRECTION OUTPUT ;
    USE SIGNAL ;
    PORT
      LAYER M5 ;
        RECT  28.848 30.132 28.872 30.216 ;
    END
  END b[57]
  PIN b[58]
    DIRECTION OUTPUT ;
    USE SIGNAL ;
    PORT
      LAYER M5 ;
        RECT  28.944 30.132 28.968 30.216 ;
    END
  END b[58]
  PIN b[59]
    DIRECTION OUTPUT ;
    USE SIGNAL ;
    PORT
      LAYER M5 ;
        RECT  29.04 30.132 29.064 30.216 ;
    END
  END b[59]
  PIN b[5]
    DIRECTION OUTPUT ;
    USE SIGNAL ;
    PORT
      LAYER M3 ;
        RECT  28.908 30.179 28.926 30.216 ;
    END
  END b[5]
  PIN b[60]
    DIRECTION OUTPUT ;
    USE SIGNAL ;
    PORT
      LAYER M5 ;
        RECT  29.136 30.132 29.16 30.216 ;
    END
  END b[60]
  PIN b[61]
    DIRECTION OUTPUT ;
    USE SIGNAL ;
    PORT
      LAYER M5 ;
        RECT  29.232 30.132 29.256 30.216 ;
    END
  END b[61]
  PIN b[62]
    DIRECTION OUTPUT ;
    USE SIGNAL ;
    PORT
      LAYER M5 ;
        RECT  29.328 30.132 29.352 30.216 ;
    END
  END b[62]
  PIN b[63]
    DIRECTION OUTPUT ;
    USE SIGNAL ;
    PORT
      LAYER M5 ;
        RECT  29.424 30.132 29.448 30.216 ;
    END
  END b[63]
  PIN b[64]
    DIRECTION OUTPUT ;
    USE SIGNAL ;
    PORT
      LAYER M5 ;
        RECT  32.592 30.132 32.616 30.216 ;
    END
  END b[64]
  PIN b[65]
    DIRECTION OUTPUT ;
    USE SIGNAL ;
    PORT
      LAYER M5 ;
        RECT  32.688 30.132 32.712 30.216 ;
    END
  END b[65]
  PIN b[66]
    DIRECTION OUTPUT ;
    USE SIGNAL ;
    PORT
      LAYER M5 ;
        RECT  32.784 30.132 32.808 30.216 ;
    END
  END b[66]
  PIN b[67]
    DIRECTION OUTPUT ;
    USE SIGNAL ;
    PORT
      LAYER M5 ;
        RECT  32.88 30.132 32.904 30.216 ;
    END
  END b[67]
  PIN b[68]
    DIRECTION OUTPUT ;
    USE SIGNAL ;
    PORT
      LAYER M5 ;
        RECT  32.976 30.132 33 30.216 ;
    END
  END b[68]
  PIN b[69]
    DIRECTION OUTPUT ;
    USE SIGNAL ;
    PORT
      LAYER M5 ;
        RECT  33.072 30.132 33.096 30.216 ;
    END
  END b[69]
  PIN b[6]
    DIRECTION OUTPUT ;
    USE SIGNAL ;
    PORT
      LAYER M3 ;
        RECT  28.98 30.179 28.998 30.216 ;
    END
  END b[6]
  PIN b[70]
    DIRECTION OUTPUT ;
    USE SIGNAL ;
    PORT
      LAYER M5 ;
        RECT  33.168 30.132 33.192 30.216 ;
    END
  END b[70]
  PIN b[71]
    DIRECTION OUTPUT ;
    USE SIGNAL ;
    PORT
      LAYER M5 ;
        RECT  33.264 30.132 33.288 30.216 ;
    END
  END b[71]
  PIN b[72]
    DIRECTION OUTPUT ;
    USE SIGNAL ;
    PORT
      LAYER M5 ;
        RECT  33.36 30.132 33.384 30.216 ;
    END
  END b[72]
  PIN b[73]
    DIRECTION OUTPUT ;
    USE SIGNAL ;
    PORT
      LAYER M5 ;
        RECT  33.456 30.132 33.48 30.216 ;
    END
  END b[73]
  PIN b[74]
    DIRECTION OUTPUT ;
    USE SIGNAL ;
    PORT
      LAYER M5 ;
        RECT  33.552 30.132 33.576 30.216 ;
    END
  END b[74]
  PIN b[75]
    DIRECTION OUTPUT ;
    USE SIGNAL ;
    PORT
      LAYER M5 ;
        RECT  33.648 30.132 33.672 30.216 ;
    END
  END b[75]
  PIN b[76]
    DIRECTION OUTPUT ;
    USE SIGNAL ;
    PORT
      LAYER M5 ;
        RECT  33.744 30.132 33.768 30.216 ;
    END
  END b[76]
  PIN b[77]
    DIRECTION OUTPUT ;
    USE SIGNAL ;
    PORT
      LAYER M5 ;
        RECT  33.84 30.132 33.864 30.216 ;
    END
  END b[77]
  PIN b[78]
    DIRECTION OUTPUT ;
    USE SIGNAL ;
    PORT
      LAYER M5 ;
        RECT  33.936 30.132 33.96 30.216 ;
    END
  END b[78]
  PIN b[79]
    DIRECTION OUTPUT ;
    USE SIGNAL ;
    PORT
      LAYER M5 ;
        RECT  34.032 30.132 34.056 30.216 ;
    END
  END b[79]
  PIN b[7]
    DIRECTION OUTPUT ;
    USE SIGNAL ;
    PORT
      LAYER M3 ;
        RECT  29.052 30.179 29.07 30.216 ;
    END
  END b[7]
  PIN b[80]
    DIRECTION OUTPUT ;
    USE SIGNAL ;
    PORT
      LAYER M5 ;
        RECT  34.128 30.132 34.152 30.216 ;
    END
  END b[80]
  PIN b[81]
    DIRECTION OUTPUT ;
    USE SIGNAL ;
    PORT
      LAYER M5 ;
        RECT  34.224 30.132 34.248 30.216 ;
    END
  END b[81]
  PIN b[82]
    DIRECTION OUTPUT ;
    USE SIGNAL ;
    PORT
      LAYER M5 ;
        RECT  34.32 30.132 34.344 30.216 ;
    END
  END b[82]
  PIN b[83]
    DIRECTION OUTPUT ;
    USE SIGNAL ;
    PORT
      LAYER M5 ;
        RECT  34.416 30.132 34.44 30.216 ;
    END
  END b[83]
  PIN b[84]
    DIRECTION OUTPUT ;
    USE SIGNAL ;
    PORT
      LAYER M5 ;
        RECT  34.512 30.132 34.536 30.216 ;
    END
  END b[84]
  PIN b[85]
    DIRECTION OUTPUT ;
    USE SIGNAL ;
    PORT
      LAYER M5 ;
        RECT  34.608 30.132 34.632 30.216 ;
    END
  END b[85]
  PIN b[86]
    DIRECTION OUTPUT ;
    USE SIGNAL ;
    PORT
      LAYER M5 ;
        RECT  34.704 30.132 34.728 30.216 ;
    END
  END b[86]
  PIN b[87]
    DIRECTION OUTPUT ;
    USE SIGNAL ;
    PORT
      LAYER M5 ;
        RECT  34.8 30.132 34.824 30.216 ;
    END
  END b[87]
  PIN b[88]
    DIRECTION OUTPUT ;
    USE SIGNAL ;
    PORT
      LAYER M5 ;
        RECT  34.896 30.132 34.92 30.216 ;
    END
  END b[88]
  PIN b[89]
    DIRECTION OUTPUT ;
    USE SIGNAL ;
    PORT
      LAYER M5 ;
        RECT  34.992 30.132 35.016 30.216 ;
    END
  END b[89]
  PIN b[8]
    DIRECTION OUTPUT ;
    USE SIGNAL ;
    PORT
      LAYER M3 ;
        RECT  29.124 30.179 29.142 30.216 ;
    END
  END b[8]
  PIN b[90]
    DIRECTION OUTPUT ;
    USE SIGNAL ;
    PORT
      LAYER M5 ;
        RECT  35.088 30.132 35.112 30.216 ;
    END
  END b[90]
  PIN b[91]
    DIRECTION OUTPUT ;
    USE SIGNAL ;
    PORT
      LAYER M5 ;
        RECT  35.184 30.132 35.208 30.216 ;
    END
  END b[91]
  PIN b[92]
    DIRECTION OUTPUT ;
    USE SIGNAL ;
    PORT
      LAYER M5 ;
        RECT  35.28 30.132 35.304 30.216 ;
    END
  END b[92]
  PIN b[93]
    DIRECTION OUTPUT ;
    USE SIGNAL ;
    PORT
      LAYER M5 ;
        RECT  35.376 30.132 35.4 30.216 ;
    END
  END b[93]
  PIN b[94]
    DIRECTION OUTPUT ;
    USE SIGNAL ;
    PORT
      LAYER M5 ;
        RECT  35.472 30.132 35.496 30.216 ;
    END
  END b[94]
  PIN b[95]
    DIRECTION OUTPUT ;
    USE SIGNAL ;
    PORT
      LAYER M5 ;
        RECT  35.568 30.132 35.592 30.216 ;
    END
  END b[95]
  PIN b[96]
    DIRECTION OUTPUT ;
    USE SIGNAL ;
    PORT
      LAYER M5 ;
        RECT  29.52 30.132 29.544 30.216 ;
    END
  END b[96]
  PIN b[97]
    DIRECTION OUTPUT ;
    USE SIGNAL ;
    PORT
      LAYER M5 ;
        RECT  29.616 30.132 29.64 30.216 ;
    END
  END b[97]
  PIN b[98]
    DIRECTION OUTPUT ;
    USE SIGNAL ;
    PORT
      LAYER M5 ;
        RECT  29.712 30.132 29.736 30.216 ;
    END
  END b[98]
  PIN b[99]
    DIRECTION OUTPUT ;
    USE SIGNAL ;
    PORT
      LAYER M5 ;
        RECT  29.808 30.132 29.832 30.216 ;
    END
  END b[99]
  PIN b[9]
    DIRECTION OUTPUT ;
    USE SIGNAL ;
    PORT
      LAYER M3 ;
        RECT  29.196 30.179 29.214 30.216 ;
    END
  END b[9]
  PIN ck_o
    DIRECTION OUTPUT ;
    USE SIGNAL ;
    PORT
      LAYER M4 ;
        RECT  0 15.312 0.084 15.336 ;
    END
  END ck_o
  PIN ckf
    DIRECTION INPUT ;
    USE SIGNAL ;
    PORT
      LAYER M4 ;
        RECT  0 15.408 0.084 15.432 ;
    END
  END ckf
  PIN ea
    DIRECTION INPUT ;
    USE SIGNAL ;
    PORT
      LAYER M4 ;
        RECT  64.692 19.152 64.776 19.176 ;
    END
  END ea
  PIN eb
    DIRECTION OUTPUT ;
    USE SIGNAL ;
    PORT
      LAYER M5 ;
        RECT  38.64 30.132 38.664 30.216 ;
    END
  END eb
  PIN VDD
    DIRECTION INOUT ;
    USE POWER ;
    PORT
      LAYER M5 ;
        RECT  61.992 2.151 62.112 27.833 ;
        RECT  59.292 2.151 59.412 27.833 ;
        RECT  56.592 2.151 56.712 27.833 ;
        RECT  53.892 2.151 54.012 27.833 ;
        RECT  51.192 2.151 51.312 27.833 ;
        RECT  48.492 2.151 48.612 27.833 ;
        RECT  45.792 2.151 45.912 27.833 ;
        RECT  43.092 2.151 43.212 27.833 ;
        RECT  40.392 2.151 40.512 27.833 ;
        RECT  37.692 2.151 37.812 27.833 ;
        RECT  34.992 2.151 35.112 27.833 ;
        RECT  32.292 2.151 32.412 27.833 ;
        RECT  29.592 2.151 29.712 27.833 ;
        RECT  26.892 2.151 27.012 27.833 ;
        RECT  24.192 2.151 24.312 27.833 ;
        RECT  21.492 2.151 21.612 27.833 ;
        RECT  18.792 2.151 18.912 27.833 ;
        RECT  16.092 2.151 16.212 27.833 ;
        RECT  13.392 2.151 13.512 27.833 ;
        RECT  10.692 2.151 10.812 27.833 ;
        RECT  7.992 2.151 8.112 27.833 ;
        RECT  5.292 2.151 5.412 27.833 ;
        RECT  2.592 2.151 2.712 27.833 ;
    END
  END VDD
  PIN VSS
    DIRECTION INOUT ;
    USE GROUND ;
    PORT
      LAYER M5 ;
        RECT  61.8 2.137 61.92 27.819 ;
        RECT  59.1 2.137 59.22 27.819 ;
        RECT  56.4 2.137 56.52 27.819 ;
        RECT  53.7 2.137 53.82 27.819 ;
        RECT  51 2.137 51.12 27.819 ;
        RECT  48.3 2.137 48.42 27.819 ;
        RECT  45.6 2.137 45.72 27.819 ;
        RECT  42.9 2.137 43.02 27.819 ;
        RECT  40.2 2.137 40.32 27.819 ;
        RECT  37.5 2.137 37.62 27.819 ;
        RECT  34.8 2.137 34.92 27.819 ;
        RECT  32.1 2.137 32.22 27.819 ;
        RECT  29.4 2.137 29.52 27.819 ;
        RECT  26.7 2.137 26.82 27.819 ;
        RECT  24 2.137 24.12 27.819 ;
        RECT  21.3 2.137 21.42 27.819 ;
        RECT  18.6 2.137 18.72 27.819 ;
        RECT  15.9 2.137 16.02 27.819 ;
        RECT  13.2 2.137 13.32 27.819 ;
        RECT  10.5 2.137 10.62 27.819 ;
        RECT  7.8 2.137 7.92 27.819 ;
        RECT  5.1 2.137 5.22 27.819 ;
        RECT  2.4 2.137 2.52 27.819 ;
    END
  END VSS
  OBS
    LAYER RVTN ;
     RECT  2.16 2.16 62.586 2.295 ;
     RECT  2.16 2.565 62.586 2.835 ;
     RECT  2.16 3.105 62.586 3.375 ;
     RECT  2.16 3.645 62.586 3.915 ;
     RECT  2.16 4.185 62.586 4.455 ;
     RECT  2.16 4.725 62.586 4.995 ;
     RECT  2.16 5.265 62.586 5.535 ;
     RECT  2.16 5.805 62.586 6.075 ;
     RECT  2.16 6.345 62.586 6.615 ;
     RECT  2.16 6.885 62.586 7.155 ;
     RECT  2.16 7.425 62.586 7.695 ;
     RECT  2.16 7.965 62.586 8.235 ;
     RECT  2.16 8.505 62.586 8.775 ;
     RECT  2.16 9.045 62.586 9.315 ;
     RECT  2.16 9.585 62.586 9.855 ;
     RECT  2.16 10.125 62.586 10.395 ;
     RECT  2.16 10.665 62.586 10.935 ;
     RECT  2.16 11.205 62.586 11.475 ;
     RECT  2.16 11.745 62.586 12.015 ;
     RECT  2.16 12.285 62.586 12.555 ;
     RECT  2.16 12.825 62.586 13.095 ;
     RECT  2.16 13.365 62.586 13.635 ;
     RECT  2.16 13.905 62.586 14.175 ;
     RECT  2.16 14.445 62.586 14.715 ;
     RECT  2.16 14.985 62.586 15.255 ;
     RECT  2.16 15.525 62.586 15.795 ;
     RECT  2.16 16.065 62.586 16.335 ;
     RECT  2.16 16.605 62.586 16.875 ;
     RECT  2.16 17.145 62.586 17.415 ;
     RECT  2.16 17.685 62.586 17.955 ;
     RECT  2.16 18.225 62.586 18.495 ;
     RECT  2.16 18.765 62.586 19.035 ;
     RECT  2.16 19.305 62.586 19.575 ;
     RECT  2.16 19.845 62.586 20.115 ;
     RECT  2.16 20.385 62.586 20.655 ;
     RECT  2.16 20.925 62.586 21.195 ;
     RECT  2.16 21.465 62.586 21.735 ;
     RECT  2.16 22.005 62.586 22.275 ;
     RECT  2.16 22.545 62.586 22.815 ;
     RECT  2.16 23.085 62.586 23.355 ;
     RECT  2.16 23.625 62.586 23.895 ;
     RECT  2.16 24.165 62.586 24.435 ;
     RECT  2.16 24.705 62.586 24.975 ;
     RECT  2.16 25.245 62.586 25.515 ;
     RECT  2.16 25.785 62.586 26.055 ;
     RECT  2.16 26.325 62.586 26.595 ;
     RECT  2.16 26.865 62.586 27.135 ;
     RECT  2.16 27.405 62.586 27.675 ;
    LAYER RVTP ;
     RECT  2.16 2.295 62.586 2.565 ;
     RECT  2.16 2.835 62.586 3.105 ;
     RECT  2.16 3.375 62.586 3.645 ;
     RECT  2.16 3.915 62.586 4.185 ;
     RECT  2.16 4.455 62.586 4.725 ;
     RECT  2.16 4.995 62.586 5.265 ;
     RECT  2.16 5.535 62.586 5.805 ;
     RECT  2.16 6.075 62.586 6.345 ;
     RECT  2.16 6.615 62.586 6.885 ;
     RECT  2.16 7.155 62.586 7.425 ;
     RECT  2.16 7.695 62.586 7.965 ;
     RECT  2.16 8.235 62.586 8.505 ;
     RECT  2.16 8.775 62.586 9.045 ;
     RECT  2.16 9.315 62.586 9.585 ;
     RECT  2.16 9.855 62.586 10.125 ;
     RECT  2.16 10.395 62.586 10.665 ;
     RECT  2.16 10.935 62.586 11.205 ;
     RECT  2.16 11.475 62.586 11.745 ;
     RECT  2.16 12.015 62.586 12.285 ;
     RECT  2.16 12.555 62.586 12.825 ;
     RECT  2.16 13.095 62.586 13.365 ;
     RECT  2.16 13.635 62.586 13.905 ;
     RECT  2.16 14.175 62.586 14.445 ;
     RECT  2.16 14.715 62.586 14.985 ;
     RECT  2.16 15.255 62.586 15.525 ;
     RECT  2.16 15.795 62.586 16.065 ;
     RECT  2.16 16.335 62.586 16.605 ;
     RECT  2.16 16.875 62.586 17.145 ;
     RECT  2.16 17.415 62.586 17.685 ;
     RECT  2.16 17.955 62.586 18.225 ;
     RECT  2.16 18.495 62.586 18.765 ;
     RECT  2.16 19.035 62.586 19.305 ;
     RECT  2.16 19.575 62.586 19.845 ;
     RECT  2.16 20.115 62.586 20.385 ;
     RECT  2.16 20.655 62.586 20.925 ;
     RECT  2.16 21.195 62.586 21.465 ;
     RECT  2.16 21.735 62.586 22.005 ;
     RECT  2.16 22.275 62.586 22.545 ;
     RECT  2.16 22.815 62.586 23.085 ;
     RECT  2.16 23.355 62.586 23.625 ;
     RECT  2.16 23.895 62.586 24.165 ;
     RECT  2.16 24.435 62.586 24.705 ;
     RECT  2.16 24.975 62.586 25.245 ;
     RECT  2.16 25.515 62.586 25.785 ;
     RECT  2.16 26.055 62.586 26.325 ;
     RECT  2.16 26.595 62.586 26.865 ;
     RECT  2.16 27.135 62.586 27.405 ;
     RECT  2.16 27.675 62.586 27.81 ;
    LAYER M1 ;
     RECT  2.16 2.151 62.586 27.819 ;
    LAYER M2 ;
     RECT  2.16 2.151 28.543 27.819 ;
     RECT  28.543 30.15 28.615 30.168 ;
     RECT  28.615 30.078 29.119 30.168 ;
     RECT  29.119 30.006 30.199 30.168 ;
     RECT  30.199 29.961 30.451 30.168 ;
     RECT  28.543 2.151 30.695 27.864 ;
     RECT  30.451 29.916 30.731 30.168 ;
     RECT  30.731 30.15 31.091 30.168 ;
     RECT  30.695 2.151 62.586 27.819 ;
     RECT  62.586 6.696 62.699 19.638 ;
     RECT  62.699 6.696 63.311 19.062 ;
     RECT  63.311 12.366 63.347 13.392 ;
     RECT  63.311 17.658 63.347 19.062 ;
     RECT  63.311 15.966 63.851 16.749 ;
     RECT  63.311 6.696 63.887 7.614 ;
     RECT  63.311 8.442 63.887 8.874 ;
     RECT  63.311 9.63 63.887 11.196 ;
     RECT  63.347 12.366 63.887 12.384 ;
     RECT  63.347 13.374 63.887 13.392 ;
     RECT  63.851 16.002 63.887 16.749 ;
     RECT  63.347 18.306 63.887 19.062 ;
     RECT  63.887 6.894 63.923 7.614 ;
     RECT  63.887 8.442 63.923 8.73 ;
     RECT  63.887 10.404 63.923 10.422 ;
     RECT  63.311 14.922 63.923 15.174 ;
     RECT  63.887 16.731 63.923 16.749 ;
     RECT  63.887 19.044 63.923 19.062 ;
     RECT  63.923 14.922 63.959 14.94 ;
     RECT  64.651 7.506 64.751 7.524 ;
     RECT  64.651 10.206 64.751 10.224 ;
     RECT  64.651 12.186 64.751 12.204 ;
     RECT  64.651 17.496 64.751 17.514 ;
    LAYER M3 ;
     RECT  2.415 2.143 2.505 2.413 ;
     RECT  5.115 2.143 5.205 2.413 ;
     RECT  7.815 2.143 7.905 2.413 ;
     RECT  10.515 2.143 10.605 2.413 ;
     RECT  13.215 2.143 13.305 2.413 ;
     RECT  15.915 2.143 16.005 2.413 ;
     RECT  18.615 2.143 18.705 2.413 ;
     RECT  21.315 2.143 21.405 2.413 ;
     RECT  24.015 2.143 24.105 2.413 ;
     RECT  26.715 2.143 26.805 2.413 ;
     RECT  29.415 2.143 29.505 2.413 ;
     RECT  32.115 2.143 32.205 2.413 ;
     RECT  34.815 2.143 34.905 2.413 ;
     RECT  37.515 2.143 37.605 2.413 ;
     RECT  40.215 2.143 40.305 2.413 ;
     RECT  42.915 2.143 43.005 2.413 ;
     RECT  45.615 2.143 45.705 2.413 ;
     RECT  48.315 2.143 48.405 2.413 ;
     RECT  51.015 2.143 51.105 2.413 ;
     RECT  53.715 2.143 53.805 2.413 ;
     RECT  56.415 2.143 56.505 2.413 ;
     RECT  59.115 2.143 59.205 2.413 ;
     RECT  61.815 2.143 61.905 2.413 ;
     RECT  59.115 2.413 59.397 6.547 ;
     RECT  58.824 6.547 59.922 6.583 ;
     RECT  61.815 2.413 62.097 6.583 ;
     RECT  58.788 6.583 59.922 6.655 ;
     RECT  58.14 6.655 59.922 6.691 ;
     RECT  61.815 6.583 62.154 6.781 ;
     RECT  56.415 2.413 56.697 6.808 ;
     RECT  63.864 6.691 63.882 6.817 ;
     RECT  58.14 6.691 59.994 6.845 ;
     RECT  56.415 6.808 56.862 6.853 ;
     RECT  28.224 6.691 28.242 6.889 ;
     RECT  63.828 6.817 63.882 6.889 ;
     RECT  55.8 6.853 56.862 6.925 ;
     RECT  61.704 6.781 62.154 6.925 ;
     RECT  27.9 6.889 28.242 6.961 ;
     RECT  60.768 6.889 60.786 6.961 ;
     RECT  61.704 6.925 62.19 6.961 ;
     RECT  58.752 6.845 59.994 7.087 ;
     RECT  60.768 6.961 62.19 7.087 ;
     RECT  55.728 6.925 57.474 7.195 ;
     RECT  42.915 2.413 43.197 7.231 ;
     RECT  58.752 7.087 62.19 7.231 ;
     RECT  26.715 2.413 26.997 7.321 ;
     RECT  27.72 6.961 28.242 7.321 ;
     RECT  42.624 7.231 43.197 7.349 ;
     RECT  30.708 6.925 30.726 7.421 ;
     RECT  54.72 6.853 54.738 7.429 ;
     RECT  55.476 7.195 57.474 7.429 ;
     RECT  63.828 6.889 63.918 7.435 ;
     RECT  64.728 7.483 64.746 7.501 ;
     RECT  64.656 7.501 64.746 7.529 ;
     RECT  64.656 7.529 64.674 7.565 ;
     RECT  58.752 7.231 62.442 7.591 ;
     RECT  52.56 7.501 52.578 7.619 ;
     RECT  51.015 2.413 51.297 7.627 ;
     RECT  54.72 7.429 57.474 7.627 ;
     RECT  58.464 7.591 62.442 7.627 ;
     RECT  63.288 7.435 63.918 7.627 ;
     RECT  50.724 7.627 51.297 7.727 ;
     RECT  54.72 7.627 63.918 7.763 ;
     RECT  26.715 7.321 28.242 7.771 ;
     RECT  29.415 2.413 29.697 7.771 ;
     RECT  54.72 7.763 62.766 7.799 ;
     RECT  58.32 7.799 62.766 8.573 ;
     RECT  40.215 2.413 40.497 8.581 ;
     RECT  51.015 7.727 51.297 8.581 ;
     RECT  54.72 7.799 57.474 8.581 ;
     RECT  58.32 8.573 59.397 8.581 ;
     RECT  63.864 7.763 63.918 8.735 ;
     RECT  30.78 8.707 30.798 8.743 ;
     RECT  38.772 8.707 38.79 8.807 ;
     RECT  40.032 8.581 40.497 8.851 ;
     RECT  60.156 8.573 62.766 8.875 ;
     RECT  63.864 8.735 63.882 8.875 ;
     RECT  30.42 8.743 30.798 8.879 ;
     RECT  50.724 8.581 51.297 8.879 ;
     RECT  26.715 7.771 29.697 9.247 ;
     RECT  30.42 8.879 30.438 9.247 ;
     RECT  54.72 8.581 59.397 9.347 ;
     RECT  53.715 2.413 53.997 9.589 ;
     RECT  54.72 9.347 54.738 9.589 ;
     RECT  55.512 9.347 59.397 9.661 ;
     RECT  60.156 8.875 63.882 9.661 ;
     RECT  55.512 9.661 63.882 9.779 ;
     RECT  42.915 7.349 43.197 9.859 ;
     RECT  26.715 9.247 30.438 9.931 ;
     RECT  57.636 9.779 63.882 10.027 ;
     RECT  33.876 9.931 33.894 10.049 ;
     RECT  55.512 9.779 56.697 10.049 ;
     RECT  64.728 10.171 64.746 10.201 ;
     RECT  64.656 10.201 64.746 10.229 ;
     RECT  64.656 10.229 64.674 10.253 ;
     RECT  26.715 9.931 30.618 10.291 ;
     RECT  32.115 2.413 32.397 10.291 ;
     RECT  33.192 10.201 33.354 10.291 ;
     RECT  53.715 9.589 54.738 10.291 ;
     RECT  57.636 10.027 63.918 10.427 ;
     RECT  26.715 10.291 30.798 10.499 ;
     RECT  53.715 10.291 55.35 10.589 ;
     RECT  57.636 10.427 63.882 10.699 ;
     RECT  57.492 10.699 63.882 10.795 ;
     RECT  34.815 2.413 35.097 10.831 ;
     RECT  56.124 10.049 56.697 10.843 ;
     RECT  57.456 10.795 63.882 10.843 ;
     RECT  35.892 10.891 35.91 10.903 ;
     RECT  53.715 10.589 55.314 10.967 ;
     RECT  54.72 10.967 55.314 10.973 ;
     RECT  34.164 10.831 35.097 10.975 ;
     RECT  35.892 10.903 35.982 10.975 ;
     RECT  56.124 10.843 63.882 11.003 ;
     RECT  32.115 10.291 33.354 11.011 ;
     RECT  34.164 10.975 36.054 11.011 ;
     RECT  26.715 10.499 30.762 11.165 ;
     RECT  56.412 11.003 63.882 11.201 ;
     RECT  56.412 11.201 63.846 11.213 ;
     RECT  32.115 11.011 36.054 11.245 ;
     RECT  32.115 11.245 36.486 11.551 ;
     RECT  54.72 10.973 54.882 11.579 ;
     RECT  54.792 11.579 54.882 11.749 ;
     RECT  32.115 11.551 36.702 11.777 ;
     RECT  36.216 11.777 36.702 11.911 ;
     RECT  37.515 2.413 37.797 11.911 ;
     RECT  54.792 11.749 55.602 11.975 ;
     RECT  56.412 11.213 63.306 11.981 ;
     RECT  56.412 11.981 60.066 12.091 ;
     RECT  64.656 12.139 64.674 12.181 ;
     RECT  64.656 12.181 64.746 12.209 ;
     RECT  64.728 12.209 64.746 12.221 ;
     RECT  60.84 11.981 63.306 12.361 ;
     RECT  60.84 12.361 63.882 12.461 ;
     RECT  26.715 11.165 30.222 12.559 ;
     RECT  39.672 8.851 40.497 12.595 ;
     RECT  32.115 11.777 35.298 12.631 ;
     RECT  36.216 11.911 37.797 12.631 ;
     RECT  54.828 11.975 55.602 12.631 ;
     RECT  56.376 12.091 60.066 12.631 ;
     RECT  36.216 12.631 37.962 12.721 ;
     RECT  54.828 12.631 60.066 12.721 ;
     RECT  60.84 12.461 63.342 12.721 ;
     RECT  38.952 12.595 40.497 12.829 ;
     RECT  38.88 12.829 40.497 12.857 ;
     RECT  32.115 12.631 35.334 12.901 ;
     RECT  36.216 12.721 38.034 12.901 ;
     RECT  38.88 12.857 38.898 12.901 ;
     RECT  38.808 12.901 38.898 12.929 ;
     RECT  32.115 12.901 38.034 12.991 ;
     RECT  38.808 12.929 38.826 12.991 ;
     RECT  32.115 12.991 38.826 13.055 ;
     RECT  51.015 8.879 51.297 13.099 ;
     RECT  50.688 13.099 51.297 13.289 ;
     RECT  32.115 13.055 38.646 13.361 ;
     RECT  54.72 12.721 63.342 13.369 ;
     RECT  49.86 13.333 49.878 13.373 ;
     RECT  54.72 13.369 63.882 13.373 ;
     RECT  32.115 13.361 38.07 13.559 ;
     RECT  58.392 13.373 63.882 13.613 ;
     RECT  26.715 12.559 30.834 13.801 ;
     RECT  32.115 13.559 37.797 13.865 ;
     RECT  26.715 13.801 31.158 13.909 ;
     RECT  32.115 13.865 36.63 13.909 ;
     RECT  26.715 13.909 36.63 13.949 ;
     RECT  26.715 13.949 36.45 13.973 ;
     RECT  58.392 13.613 63.342 14.243 ;
     RECT  54.72 13.373 57.618 14.251 ;
     RECT  58.392 14.243 62.766 14.251 ;
     RECT  31.716 13.973 36.45 14.477 ;
     RECT  63.756 14.347 63.774 14.539 ;
     RECT  63.756 14.539 63.882 14.731 ;
     RECT  31.716 14.477 36.27 14.755 ;
     RECT  26.715 13.973 30.87 14.791 ;
     RECT  31.68 14.755 36.27 14.791 ;
     RECT  63.756 14.731 63.918 14.917 ;
     RECT  63.756 14.917 63.954 14.957 ;
     RECT  53.715 10.967 53.997 15.025 ;
     RECT  54.72 14.251 62.766 15.115 ;
     RECT  63.756 14.957 63.918 15.115 ;
     RECT  54.72 15.115 63.918 15.179 ;
     RECT  2.415 2.413 2.697 15.295 ;
     RECT  54.72 15.179 63.306 15.437 ;
     RECT  2.412 15.295 2.697 15.448 ;
     RECT  2.34 15.448 2.697 15.485 ;
     RECT  55.62 15.437 63.306 15.961 ;
     RECT  55.62 15.961 63.846 15.997 ;
     RECT  38.772 16.027 38.79 16.157 ;
     RECT  46.764 16.027 46.782 16.157 ;
     RECT  54.72 15.437 54.882 16.303 ;
     RECT  55.62 15.997 63.882 16.303 ;
     RECT  53.028 15.025 53.997 16.331 ;
     RECT  54.72 16.303 63.882 16.651 ;
     RECT  54.72 16.651 63.918 16.754 ;
     RECT  54.72 16.754 63.846 16.781 ;
     RECT  54.72 16.781 63.342 17.069 ;
     RECT  54.72 17.069 55.458 17.117 ;
     RECT  53.715 16.331 53.997 17.323 ;
     RECT  54.72 17.117 55.422 17.323 ;
     RECT  52.092 17.311 52.11 17.357 ;
     RECT  53.715 17.323 55.422 17.375 ;
     RECT  64.728 17.467 64.746 17.491 ;
     RECT  64.656 17.491 64.746 17.519 ;
     RECT  64.656 17.519 64.674 17.549 ;
     RECT  53.715 17.375 53.997 17.608 ;
     RECT  26.715 14.791 36.27 17.609 ;
     RECT  53.424 17.608 53.997 17.645 ;
     RECT  56.232 17.069 63.342 17.803 ;
     RECT  52.2 17.617 52.218 17.879 ;
     RECT  54.72 17.375 55.422 17.887 ;
     RECT  56.232 17.803 63.882 17.887 ;
     RECT  53.64 17.645 53.997 17.933 ;
     RECT  54.72 17.887 63.882 18.221 ;
     RECT  54.72 18.221 62.802 18.455 ;
     RECT  26.715 17.609 33.462 18.499 ;
     RECT  34.272 17.609 36.27 18.499 ;
     RECT  55.548 18.455 62.802 18.509 ;
     RECT  55.548 18.509 62.766 18.689 ;
     RECT  26.715 18.499 36.27 18.725 ;
     RECT  63.828 18.221 63.882 18.763 ;
     RECT  57.672 18.689 62.73 18.959 ;
     RECT  63.828 18.763 63.918 18.989 ;
     RECT  58.032 18.959 62.73 18.995 ;
     RECT  63.9 18.989 63.918 19.067 ;
     RECT  39.672 12.857 40.497 19.201 ;
     RECT  54.72 18.455 54.738 19.229 ;
     RECT  58.536 18.995 62.73 19.229 ;
     RECT  52.416 19.201 52.434 19.237 ;
     RECT  52.308 19.237 52.434 19.277 ;
     RECT  52.308 19.277 52.326 19.325 ;
     RECT  59.115 19.229 62.73 19.325 ;
     RECT  55.548 18.689 56.898 19.373 ;
     RECT  59.115 19.325 62.694 19.373 ;
     RECT  55.548 19.373 56.697 19.499 ;
     RECT  55.548 19.499 55.566 19.535 ;
     RECT  60.696 19.373 62.694 19.643 ;
     RECT  34.272 18.725 36.27 26.237 ;
     RECT  59.115 19.373 59.886 26.491 ;
     RECT  58.716 26.491 59.886 26.591 ;
     RECT  60.696 19.643 62.097 26.591 ;
     RECT  26.715 18.725 33.462 26.671 ;
     RECT  39.24 19.201 40.497 26.671 ;
     RECT  59.115 26.591 59.886 26.671 ;
     RECT  60.696 26.591 60.714 26.671 ;
     RECT  38.844 26.671 40.497 26.779 ;
     RECT  59.115 26.671 60.714 26.789 ;
     RECT  38.7 26.779 40.497 26.825 ;
     RECT  39.24 26.825 40.497 26.861 ;
     RECT  59.115 26.789 60.03 26.969 ;
     RECT  44.784 27.139 44.802 27.211 ;
     RECT  45.615 2.413 45.897 27.211 ;
     RECT  44.424 27.211 45.897 27.329 ;
     RECT  44.424 27.329 44.802 27.365 ;
     RECT  47.556 7.627 47.574 27.365 ;
     RECT  2.415 15.485 2.697 27.557 ;
     RECT  5.115 2.413 5.397 27.557 ;
     RECT  7.815 2.413 8.097 27.557 ;
     RECT  10.515 2.413 10.797 27.557 ;
     RECT  13.215 2.413 13.497 27.557 ;
     RECT  15.915 2.413 16.197 27.557 ;
     RECT  18.615 2.413 18.897 27.557 ;
     RECT  21.315 2.413 21.597 27.557 ;
     RECT  24.015 2.413 24.297 27.557 ;
     RECT  37.515 13.865 37.797 27.557 ;
     RECT  39.492 26.861 40.497 27.557 ;
     RECT  45.615 27.329 45.897 27.557 ;
     RECT  48.315 2.413 48.597 27.557 ;
     RECT  51.015 13.289 51.297 27.557 ;
     RECT  53.715 17.933 53.997 27.557 ;
     RECT  56.415 19.499 56.697 27.557 ;
     RECT  59.115 26.969 59.958 27.557 ;
     RECT  61.815 26.591 62.097 27.557 ;
     RECT  39.492 27.557 39.51 27.635 ;
     RECT  42.408 9.859 43.197 27.635 ;
     RECT  37.707 27.557 37.797 27.643 ;
     RECT  59.307 27.557 59.958 27.671 ;
     RECT  44.424 27.365 44.442 27.725 ;
     RECT  37.707 27.643 37.89 27.773 ;
     RECT  40.32 27.557 40.497 27.773 ;
     RECT  2.607 27.557 2.697 27.827 ;
     RECT  5.307 27.557 5.397 27.827 ;
     RECT  8.007 27.557 8.097 27.827 ;
     RECT  10.707 27.557 10.797 27.827 ;
     RECT  13.407 27.557 13.497 27.827 ;
     RECT  16.107 27.557 16.197 27.827 ;
     RECT  18.807 27.557 18.897 27.827 ;
     RECT  21.507 27.557 21.597 27.827 ;
     RECT  24.207 27.557 24.297 27.827 ;
     RECT  26.676 26.671 33.462 27.827 ;
     RECT  34.524 26.237 36.27 27.827 ;
     RECT  37.707 27.773 37.797 27.827 ;
     RECT  40.407 27.773 40.497 27.827 ;
     RECT  42.552 27.635 43.197 27.827 ;
     RECT  45.807 27.557 45.897 27.827 ;
     RECT  48.507 27.557 48.597 27.827 ;
     RECT  51.207 27.557 51.297 27.827 ;
     RECT  53.907 27.557 53.997 27.827 ;
     RECT  56.607 27.557 56.697 27.827 ;
     RECT  59.307 27.671 59.397 27.827 ;
     RECT  62.007 27.557 62.097 27.827 ;
     RECT  32.868 27.827 33.462 27.917 ;
     RECT  34.524 27.827 34.542 27.917 ;
     RECT  38.736 27.751 38.754 27.965 ;
     RECT  26.676 27.827 32.058 28.013 ;
     RECT  42.552 27.827 42.57 28.205 ;
     RECT  26.676 28.013 32.022 28.493 ;
     RECT  32.868 27.917 32.886 28.493 ;
     RECT  35.676 27.827 36.27 28.493 ;
     RECT  26.856 28.493 27.594 29.069 ;
     RECT  36.252 28.493 36.27 29.597 ;
     RECT  27.576 29.069 27.594 29.645 ;
     RECT  28.692 28.493 32.022 29.693 ;
     RECT  27.288 29.851 27.306 29.947 ;
     RECT  28.692 29.693 31.806 30.073 ;
     RECT  27.18 29.947 27.306 30.077 ;
     RECT  27.18 30.077 27.198 30.125 ;
     RECT  28.62 30.073 31.806 30.125 ;
     RECT  28.62 30.125 31.086 30.145 ;
     RECT  28.548 30.145 31.086 30.173 ;
     RECT  28.548 30.173 30.798 30.204 ;
    LAYER M4 ;
     RECT  0.06 15.312 0.179 15.432 ;
     RECT  0.179 15.312 2.329 15.336 ;
     RECT  0.133 13.344 2.408 13.368 ;
     RECT  2.329 15.312 2.408 15.48 ;
     RECT  2.408 2.148 2.512 27.552 ;
     RECT  2.512 2.418 2.6 27.552 ;
     RECT  2.6 2.418 2.704 27.822 ;
     RECT  2.704 13.344 5.108 13.368 ;
     RECT  2.704 15.456 5.108 15.48 ;
     RECT  5.108 2.148 5.212 27.552 ;
     RECT  5.212 2.418 5.3 27.552 ;
     RECT  5.3 2.418 5.404 27.822 ;
     RECT  5.404 13.344 7.808 13.368 ;
     RECT  5.404 15.456 7.808 15.48 ;
     RECT  7.808 2.148 7.912 27.552 ;
     RECT  7.912 2.418 8 27.552 ;
     RECT  8 2.418 8.104 27.822 ;
     RECT  8.104 13.344 10.508 13.368 ;
     RECT  8.104 15.456 10.508 15.48 ;
     RECT  10.508 2.148 10.612 27.552 ;
     RECT  10.612 2.418 10.7 27.552 ;
     RECT  10.7 2.418 10.804 27.822 ;
     RECT  10.804 13.344 13.208 13.368 ;
     RECT  10.804 15.456 13.208 15.48 ;
     RECT  13.208 2.148 13.312 27.552 ;
     RECT  13.312 2.418 13.4 27.552 ;
     RECT  13.4 2.418 13.504 27.822 ;
     RECT  13.504 13.344 15.908 13.368 ;
     RECT  13.504 15.456 15.908 15.48 ;
     RECT  15.908 2.148 16.012 27.552 ;
     RECT  16.012 2.418 16.1 27.552 ;
     RECT  16.1 2.418 16.204 27.822 ;
     RECT  16.204 13.344 18.608 13.368 ;
     RECT  16.204 15.456 18.608 15.48 ;
     RECT  18.608 2.148 18.712 27.552 ;
     RECT  18.712 2.418 18.8 27.552 ;
     RECT  18.8 2.418 18.904 27.822 ;
     RECT  18.904 13.344 21.308 13.368 ;
     RECT  18.904 15.456 21.308 15.48 ;
     RECT  21.308 2.148 21.412 27.552 ;
     RECT  21.412 2.418 21.5 27.552 ;
     RECT  21.5 2.418 21.604 27.822 ;
     RECT  21.604 13.344 24.008 13.368 ;
     RECT  21.604 15.456 24.008 15.48 ;
     RECT  24.008 2.148 24.112 27.552 ;
     RECT  24.112 2.418 24.2 27.552 ;
     RECT  24.2 2.418 24.304 27.822 ;
     RECT  26.437 27.696 26.533 27.72 ;
     RECT  24.304 13.344 26.581 13.368 ;
     RECT  26.533 27.696 26.621 28.2 ;
     RECT  26.581 13.056 26.708 13.368 ;
     RECT  24.304 15.456 26.708 15.48 ;
     RECT  26.621 27.696 26.708 28.488 ;
     RECT  26.708 2.148 26.801 28.488 ;
     RECT  26.801 2.148 26.812 29.064 ;
     RECT  26.812 2.418 26.885 29.064 ;
     RECT  26.885 2.418 27.004 28.488 ;
     RECT  26.581 30.048 27.013 30.072 ;
     RECT  27.004 13.056 27.065 13.368 ;
     RECT  27.013 29.616 27.154 30.072 ;
     RECT  27.154 29.616 27.253 30.12 ;
     RECT  27.253 29.616 27.347 30.072 ;
     RECT  27.347 29.616 27.605 29.64 ;
     RECT  27.004 8.544 27.713 10.248 ;
     RECT  27.713 9.696 27.929 10.248 ;
     RECT  27.929 10.224 27.937 10.248 ;
     RECT  27.004 15.456 28.165 15.48 ;
     RECT  28.165 14.784 28.453 15.48 ;
     RECT  28.741 29.616 28.829 29.64 ;
     RECT  28.549 10.272 28.837 10.344 ;
     RECT  28.261 11.376 28.837 11.4 ;
     RECT  28.453 14.736 28.933 15.48 ;
     RECT  27.004 27.696 29.005 28.488 ;
     RECT  28.837 10.272 29.029 11.4 ;
     RECT  27.713 8.544 29.125 8.568 ;
     RECT  29.077 18.768 29.173 18.792 ;
     RECT  28.933 14.736 29.185 15.864 ;
     RECT  29.029 10.272 29.221 12.024 ;
     RECT  27.065 13.344 29.269 13.368 ;
     RECT  29.125 8.496 29.408 8.568 ;
     RECT  29.221 10.176 29.408 12.024 ;
     RECT  29.269 13.344 29.408 13.704 ;
     RECT  29.185 14.736 29.408 16.296 ;
     RECT  29.173 18.192 29.408 18.792 ;
     RECT  29.005 22.8 29.408 23.208 ;
     RECT  29.173 26.112 29.408 26.232 ;
     RECT  29.005 27.456 29.408 28.488 ;
     RECT  29.408 2.148 29.512 28.488 ;
     RECT  29.077 29.952 29.555 30.168 ;
     RECT  29.555 30.048 29.585 30.168 ;
     RECT  29.512 2.418 29.704 28.488 ;
     RECT  29.585 30.048 29.891 30.072 ;
     RECT  29.704 27.36 30.017 28.488 ;
     RECT  29.704 12 30.053 12.024 ;
     RECT  29.704 13.344 30.227 16.392 ;
     RECT  30.017 27.36 30.419 28.2 ;
     RECT  30.227 13.344 30.593 13.704 ;
     RECT  30.227 14.736 30.773 16.392 ;
     RECT  29.704 18.192 31.669 18.216 ;
     RECT  30.773 15.216 31.697 16.392 ;
     RECT  31.525 20.4 31.813 20.424 ;
     RECT  30.741 30.096 31.817 30.12 ;
     RECT  31.093 19.2 31.877 19.224 ;
     RECT  31.697 15.216 31.909 16.536 ;
     RECT  31.669 17.616 31.909 18.216 ;
     RECT  31.877 19.2 31.909 19.272 ;
     RECT  31.957 30.048 31.964 30.072 ;
     RECT  31.964 29.664 32.051 30.072 ;
     RECT  29.704 8.496 32.108 8.52 ;
     RECT  30.593 13.344 32.108 13.368 ;
     RECT  31.909 15.216 32.108 18.216 ;
     RECT  31.909 19.2 32.108 19.368 ;
     RECT  31.813 20.352 32.108 20.424 ;
     RECT  31.409 24.48 32.108 24.504 ;
     RECT  30.419 27.648 32.108 28.2 ;
     RECT  32.051 30.048 32.147 30.072 ;
     RECT  32.108 2.148 32.212 28.2 ;
     RECT  32.212 2.418 32.404 28.2 ;
     RECT  32.404 12.528 32.465 17.112 ;
     RECT  32.404 27.36 32.485 28.2 ;
     RECT  32.485 27.36 32.627 28.488 ;
     RECT  32.465 15.456 32.645 17.112 ;
     RECT  32.404 20.352 32.825 20.376 ;
     RECT  32.627 27.648 32.897 28.488 ;
     RECT  32.465 12.528 33.637 14.424 ;
     RECT  32.645 15.456 33.637 16.392 ;
     RECT  33.637 12.528 34.021 16.392 ;
     RECT  32.404 8.496 34.808 8.52 ;
     RECT  34.021 12 34.808 16.392 ;
     RECT  34.556 22.8 34.808 22.824 ;
     RECT  34.213 26.208 34.808 26.232 ;
     RECT  32.897 27.648 34.808 28.2 ;
     RECT  34.789 29.808 34.885 29.832 ;
     RECT  34.808 2.148 34.912 28.2 ;
     RECT  34.912 2.418 34.981 28.2 ;
     RECT  34.885 29.712 35.077 29.832 ;
     RECT  34.981 2.418 35.104 28.488 ;
     RECT  35.077 29.664 35.125 29.832 ;
     RECT  35.125 29.568 35.173 29.976 ;
     RECT  35.104 12.768 35.273 16.392 ;
     RECT  35.273 12.768 35.345 13.944 ;
     RECT  35.104 25.056 35.345 25.08 ;
     RECT  35.104 22.8 35.363 22.824 ;
     RECT  35.173 29.568 35.363 30.072 ;
     RECT  35.104 26.736 35.633 28.488 ;
     RECT  35.633 27.648 35.705 28.488 ;
     RECT  35.273 14.928 35.777 16.392 ;
     RECT  35.777 15.36 35.921 16.392 ;
     RECT  35.104 10.896 36.065 11.016 ;
     RECT  35.104 17.616 36.209 17.64 ;
     RECT  35.363 29.568 36.281 29.592 ;
     RECT  35.104 8.496 37.508 8.52 ;
     RECT  36.065 10.896 37.508 10.92 ;
     RECT  35.345 13.056 37.508 13.944 ;
     RECT  35.921 15.456 37.508 16.392 ;
     RECT  35.705 27.648 37.508 28.2 ;
     RECT  37.508 2.148 37.612 28.2 ;
     RECT  37.612 2.418 37.804 28.2 ;
     RECT  37.804 15.456 38.243 16.392 ;
     RECT  37.804 26.784 38.771 28.2 ;
     RECT  37.804 8.496 40.208 8.52 ;
     RECT  37.804 10.896 40.208 10.92 ;
     RECT  37.804 13.344 40.208 13.368 ;
     RECT  38.243 16.032 40.208 16.392 ;
     RECT  37.804 17.664 40.208 17.688 ;
     RECT  39.769 19.248 40.208 19.272 ;
     RECT  38.771 27.696 40.208 28.2 ;
     RECT  40.208 2.148 40.312 28.2 ;
     RECT  40.312 2.418 40.504 28.2 ;
     RECT  40.504 27.648 42.581 28.2 ;
     RECT  40.504 8.496 42.908 8.52 ;
     RECT  40.504 10.896 42.908 10.92 ;
     RECT  40.504 13.344 42.908 13.368 ;
     RECT  40.504 16.032 42.908 16.392 ;
     RECT  40.504 17.664 42.908 17.688 ;
     RECT  40.504 19.248 42.908 19.272 ;
     RECT  42.581 27.648 42.908 27.822 ;
     RECT  42.908 2.148 43.012 27.822 ;
     RECT  43.012 2.418 43.204 27.822 ;
     RECT  43.204 27.696 44.453 27.72 ;
     RECT  43.204 8.496 45.608 8.52 ;
     RECT  43.204 10.896 45.608 10.92 ;
     RECT  43.204 13.344 45.608 13.368 ;
     RECT  43.204 16.032 45.608 16.392 ;
     RECT  43.204 17.664 45.608 17.688 ;
     RECT  43.204 19.248 45.608 19.272 ;
     RECT  45.608 2.148 45.712 27.552 ;
     RECT  45.712 2.418 45.8 27.552 ;
     RECT  45.8 2.418 45.904 27.822 ;
     RECT  45.904 8.496 48.308 8.52 ;
     RECT  45.904 10.896 48.308 10.92 ;
     RECT  45.904 13.344 48.308 13.368 ;
     RECT  45.904 16.032 48.308 16.392 ;
     RECT  45.904 17.664 48.308 17.688 ;
     RECT  45.904 19.248 48.308 19.272 ;
     RECT  48.308 2.148 48.412 27.552 ;
     RECT  48.412 2.418 48.5 27.552 ;
     RECT  48.5 2.418 48.604 27.822 ;
     RECT  48.604 13.344 49.889 13.368 ;
     RECT  48.604 8.496 51.008 8.52 ;
     RECT  48.604 10.896 51.008 10.92 ;
     RECT  50.677 13.104 51.008 13.128 ;
     RECT  48.604 16.032 51.008 16.392 ;
     RECT  48.604 17.664 51.008 17.688 ;
     RECT  48.604 19.248 51.008 19.272 ;
     RECT  51.008 2.148 51.112 27.552 ;
     RECT  51.112 2.418 51.2 27.552 ;
     RECT  51.2 2.418 51.304 27.822 ;
     RECT  51.304 16.032 52.163 17.928 ;
     RECT  51.304 19.248 52.297 19.272 ;
     RECT  52.297 19.248 52.445 19.32 ;
     RECT  52.163 17.904 53.413 17.928 ;
     RECT  51.304 8.496 53.708 8.52 ;
     RECT  51.304 10.896 53.708 10.92 ;
     RECT  51.304 13.104 53.708 13.128 ;
     RECT  52.163 16.032 53.708 16.392 ;
     RECT  53.413 17.616 53.708 17.928 ;
     RECT  52.445 19.296 53.708 19.32 ;
     RECT  53.708 2.148 53.812 27.552 ;
     RECT  53.812 2.418 53.9 27.552 ;
     RECT  53.9 2.418 54.004 27.822 ;
     RECT  54.004 10.896 55.177 10.92 ;
     RECT  54.004 16.032 55.177 17.928 ;
     RECT  55.177 10.56 55.285 10.92 ;
     RECT  54.004 13.104 55.393 13.128 ;
     RECT  54.004 19.296 55.645 19.32 ;
     RECT  55.573 11.952 55.753 11.976 ;
     RECT  55.393 13.104 55.753 13.704 ;
     RECT  55.285 10.56 55.789 10.968 ;
     RECT  55.177 15.408 55.897 17.928 ;
     RECT  55.897 15.264 55.905 17.928 ;
     RECT  55.645 18.96 55.905 19.32 ;
     RECT  56.365 7.344 56.408 7.368 ;
     RECT  54.004 8.496 56.408 8.52 ;
     RECT  55.789 9.792 56.408 10.968 ;
     RECT  55.753 11.952 56.408 13.704 ;
     RECT  55.905 15.264 56.408 19.32 ;
     RECT  56.408 2.148 56.512 27.552 ;
     RECT  56.512 2.418 56.6 27.552 ;
     RECT  56.6 2.418 56.704 27.822 ;
     RECT  56.704 6.816 57.305 19.32 ;
     RECT  57.305 6.816 57.521 14.856 ;
     RECT  57.305 15.84 57.665 19.32 ;
     RECT  57.521 6.816 58.633 14.712 ;
     RECT  58.633 6.816 58.885 14.856 ;
     RECT  57.665 16.032 58.885 19.32 ;
     RECT  58.885 6.816 59.108 19.32 ;
     RECT  59.108 2.148 59.212 27.552 ;
     RECT  59.212 2.418 59.3 27.552 ;
     RECT  59.3 2.418 59.404 27.822 ;
     RECT  59.404 7.392 59.717 19.32 ;
     RECT  59.717 7.392 60.221 17.688 ;
     RECT  60.221 9.648 60.365 17.688 ;
     RECT  60.365 13.728 60.473 17.688 ;
     RECT  59.717 18.816 60.653 19.32 ;
     RECT  60.221 7.392 61.189 8.568 ;
     RECT  60.365 9.648 61.189 12.744 ;
     RECT  60.473 17.664 61.297 17.688 ;
     RECT  60.473 13.92 61.549 16.584 ;
     RECT  61.297 17.664 61.549 18.216 ;
     RECT  61.189 7.392 61.808 12.744 ;
     RECT  61.549 13.92 61.808 18.216 ;
     RECT  60.653 19.296 61.808 19.32 ;
     RECT  61.808 2.148 61.912 27.552 ;
     RECT  61.912 2.418 62 27.552 ;
     RECT  62 2.418 62.104 27.822 ;
     RECT  62.104 7.056 62.741 19.32 ;
     RECT  62.741 7.056 63.817 19.176 ;
     RECT  63.817 6.864 64.716 19.176 ;
     RECT  64.716 7.488 64.757 7.512 ;
     RECT  64.716 10.176 64.757 10.2 ;
     RECT  64.716 12.192 64.757 12.216 ;
     RECT  64.716 17.472 64.757 17.496 ;
    LAYER M5 ;
     RECT  2.4 2.137 2.52 2.151 ;
     RECT  5.1 2.137 5.22 2.151 ;
     RECT  7.8 2.137 7.92 2.151 ;
     RECT  10.5 2.137 10.62 2.151 ;
     RECT  13.2 2.137 13.32 2.151 ;
     RECT  15.9 2.137 16.02 2.151 ;
     RECT  18.6 2.137 18.72 2.151 ;
     RECT  21.3 2.137 21.42 2.151 ;
     RECT  24 2.137 24.12 2.151 ;
     RECT  26.7 2.137 26.82 2.151 ;
     RECT  29.4 2.137 29.52 2.151 ;
     RECT  32.1 2.137 32.22 2.151 ;
     RECT  34.8 2.137 34.92 2.151 ;
     RECT  37.5 2.137 37.62 2.151 ;
     RECT  40.2 2.137 40.32 2.151 ;
     RECT  42.9 2.137 43.02 2.151 ;
     RECT  45.6 2.137 45.72 2.151 ;
     RECT  48.3 2.137 48.42 2.151 ;
     RECT  51 2.137 51.12 2.151 ;
     RECT  53.7 2.137 53.82 2.151 ;
     RECT  56.4 2.137 56.52 2.151 ;
     RECT  59.1 2.137 59.22 2.151 ;
     RECT  61.8 2.137 61.92 2.151 ;
     RECT  56.4 2.151 56.712 6.805 ;
     RECT  59.1 2.151 59.412 7.381 ;
     RECT  56.4 6.805 57.048 7.619 ;
     RECT  29.4 2.151 29.712 8.485 ;
     RECT  59.1 7.381 59.544 8.531 ;
     RECT  26.7 2.151 27.012 8.533 ;
     RECT  58.08 8.149 58.104 9.061 ;
     RECT  59.1 8.531 59.412 9.061 ;
     RECT  26.7 8.533 27.528 9.685 ;
     RECT  26.7 9.685 27.816 10.213 ;
     RECT  26.7 10.213 27.912 10.261 ;
     RECT  29.136 8.485 29.712 10.261 ;
     RECT  58.08 9.061 59.412 10.355 ;
     RECT  56.4 7.619 56.712 11.941 ;
     RECT  34.8 2.151 35.112 11.989 ;
     RECT  32.1 2.151 32.412 12.517 ;
     RECT  34.032 11.989 35.112 12.517 ;
     RECT  56.4 11.941 57.048 12.853 ;
     RECT  58.08 10.355 58.104 12.853 ;
     RECT  26.7 10.261 29.712 13.045 ;
     RECT  32.1 12.517 35.112 13.045 ;
     RECT  56.304 12.853 58.104 13.283 ;
     RECT  56.4 13.283 58.104 13.571 ;
     RECT  32.1 13.045 35.208 13.669 ;
     RECT  32.1 13.669 35.256 13.861 ;
     RECT  26.592 13.045 29.712 14.005 ;
     RECT  59.1 10.355 59.412 14.197 ;
     RECT  26.592 14.005 30.216 14.725 ;
     RECT  58.848 14.197 59.412 14.867 ;
     RECT  26.592 14.725 30.6 15.301 ;
     RECT  0.144 13.333 0.168 15.443 ;
     RECT  37.5 2.151 37.812 15.445 ;
     RECT  26.592 15.301 31.08 15.973 ;
     RECT  32.1 13.861 35.496 15.973 ;
     RECT  56.4 13.571 57.528 16.211 ;
     RECT  59.1 14.867 59.412 16.501 ;
     RECT  59.1 16.501 60.168 17.123 ;
     RECT  51 2.151 51.312 17.317 ;
     RECT  55.392 17.077 55.416 17.363 ;
     RECT  37.5 15.445 38.232 17.653 ;
     RECT  51 17.317 52.152 17.939 ;
     RECT  56.4 16.211 57.048 18.085 ;
     RECT  56.4 18.085 57.624 18.229 ;
     RECT  55.968 18.229 57.624 18.995 ;
     RECT  26.592 15.973 35.496 26.725 ;
     RECT  37.5 17.653 38.76 26.819 ;
     RECT  26.592 26.725 35.592 27.685 ;
     RECT  2.4 2.151 2.712 27.819 ;
     RECT  5.1 2.151 5.412 27.819 ;
     RECT  7.8 2.151 8.112 27.819 ;
     RECT  10.5 2.151 10.812 27.819 ;
     RECT  13.2 2.151 13.512 27.819 ;
     RECT  15.9 2.151 16.212 27.819 ;
     RECT  18.6 2.151 18.912 27.819 ;
     RECT  21.3 2.151 21.612 27.819 ;
     RECT  24 2.151 24.312 27.819 ;
     RECT  37.5 26.819 37.812 27.819 ;
     RECT  40.2 2.151 40.512 27.819 ;
     RECT  42.9 2.151 43.212 27.819 ;
     RECT  45.6 2.151 45.912 27.819 ;
     RECT  48.3 2.151 48.612 27.819 ;
     RECT  51 17.939 51.312 27.819 ;
     RECT  53.7 2.151 54.012 27.819 ;
     RECT  56.4 18.995 56.712 27.819 ;
     RECT  59.1 17.123 59.412 27.819 ;
     RECT  61.8 2.151 62.112 27.819 ;
     RECT  2.592 27.819 2.712 27.833 ;
     RECT  5.292 27.819 5.412 27.833 ;
     RECT  7.992 27.819 8.112 27.833 ;
     RECT  10.692 27.819 10.812 27.833 ;
     RECT  13.392 27.819 13.512 27.833 ;
     RECT  16.092 27.819 16.212 27.833 ;
     RECT  18.792 27.819 18.912 27.833 ;
     RECT  21.492 27.819 21.612 27.833 ;
     RECT  24.192 27.819 24.312 27.833 ;
     RECT  37.692 27.819 37.812 27.833 ;
     RECT  40.392 27.819 40.512 27.833 ;
     RECT  43.092 27.819 43.212 27.833 ;
     RECT  45.792 27.819 45.912 27.833 ;
     RECT  48.492 27.819 48.612 27.833 ;
     RECT  51.192 27.819 51.312 27.833 ;
     RECT  53.892 27.819 54.012 27.833 ;
     RECT  56.592 27.819 56.712 27.833 ;
     RECT  59.292 27.819 59.412 27.833 ;
     RECT  61.992 27.819 62.112 27.833 ;
     RECT  26.448 27.685 35.592 30.16 ;
     RECT  38.64 27.925 38.664 30.16 ;
  END
END qfd_rlyh_128_EN_65x30
END LIBRARY
